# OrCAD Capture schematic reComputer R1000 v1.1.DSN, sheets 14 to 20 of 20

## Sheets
14 16 RS485_1& Isolated Power: size A3; rev: v1.0
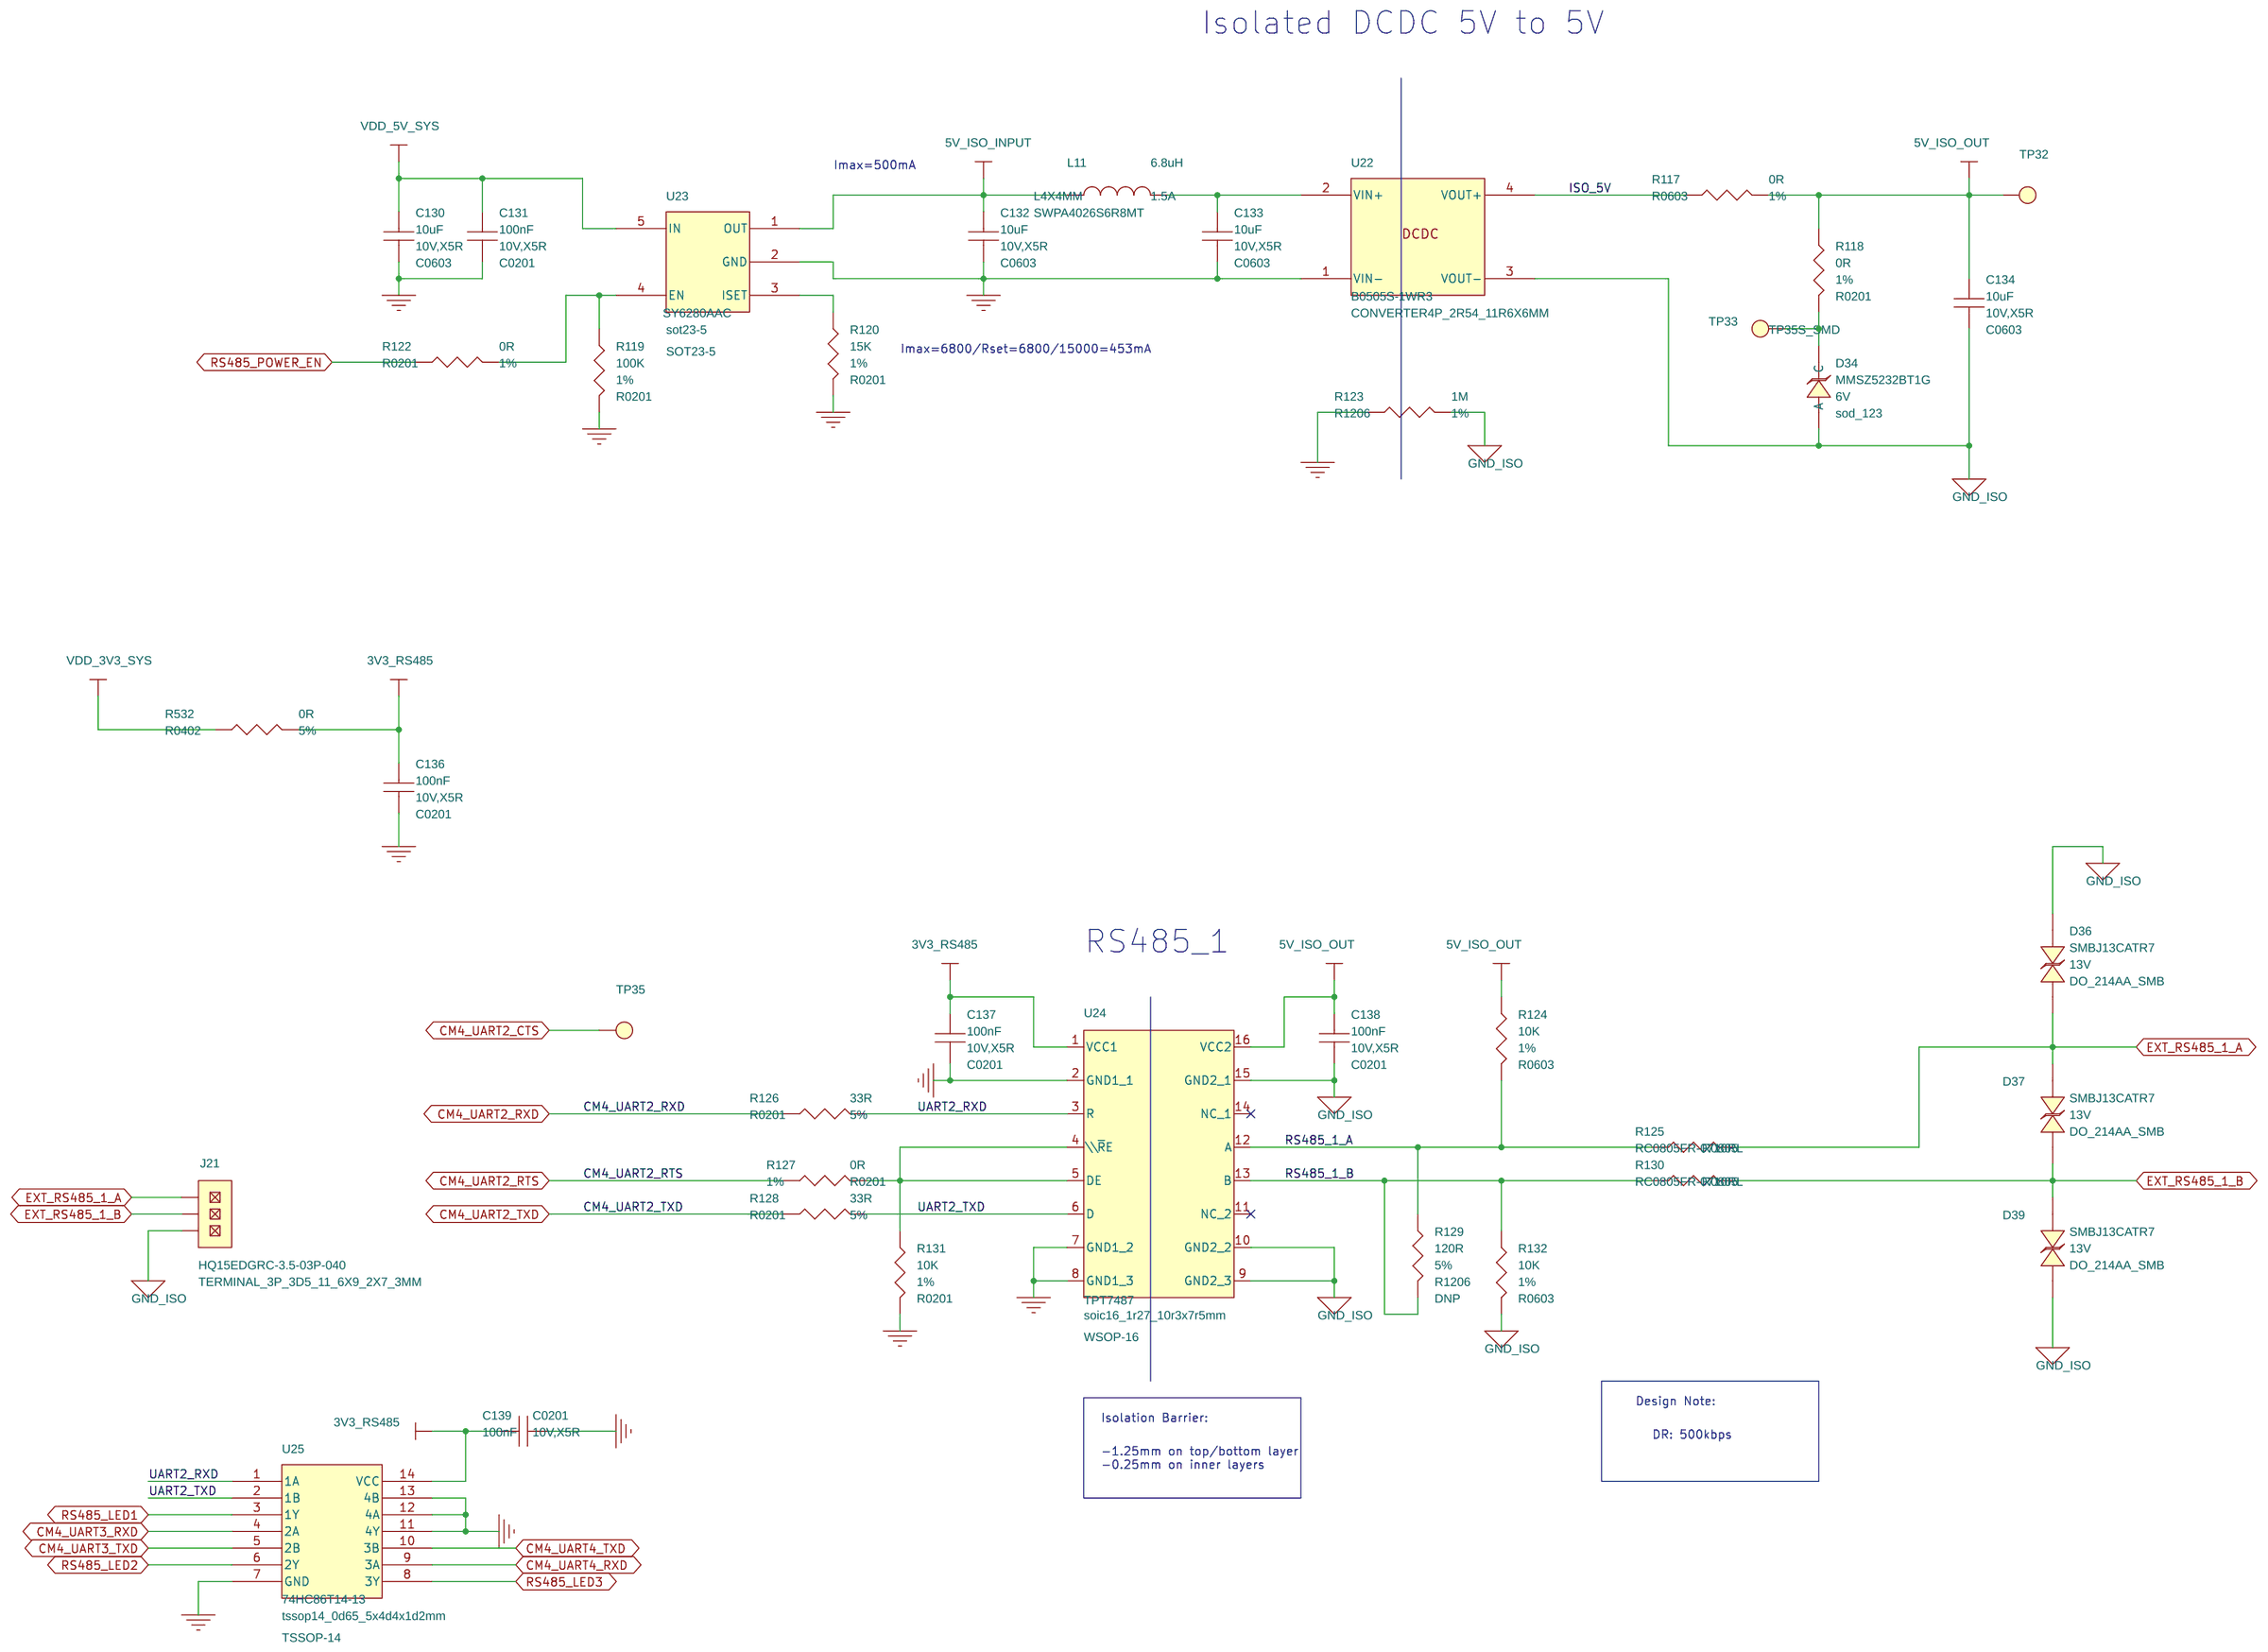
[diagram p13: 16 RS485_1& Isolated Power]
15 17 RS485 2&3: size A3; rev: v1.0
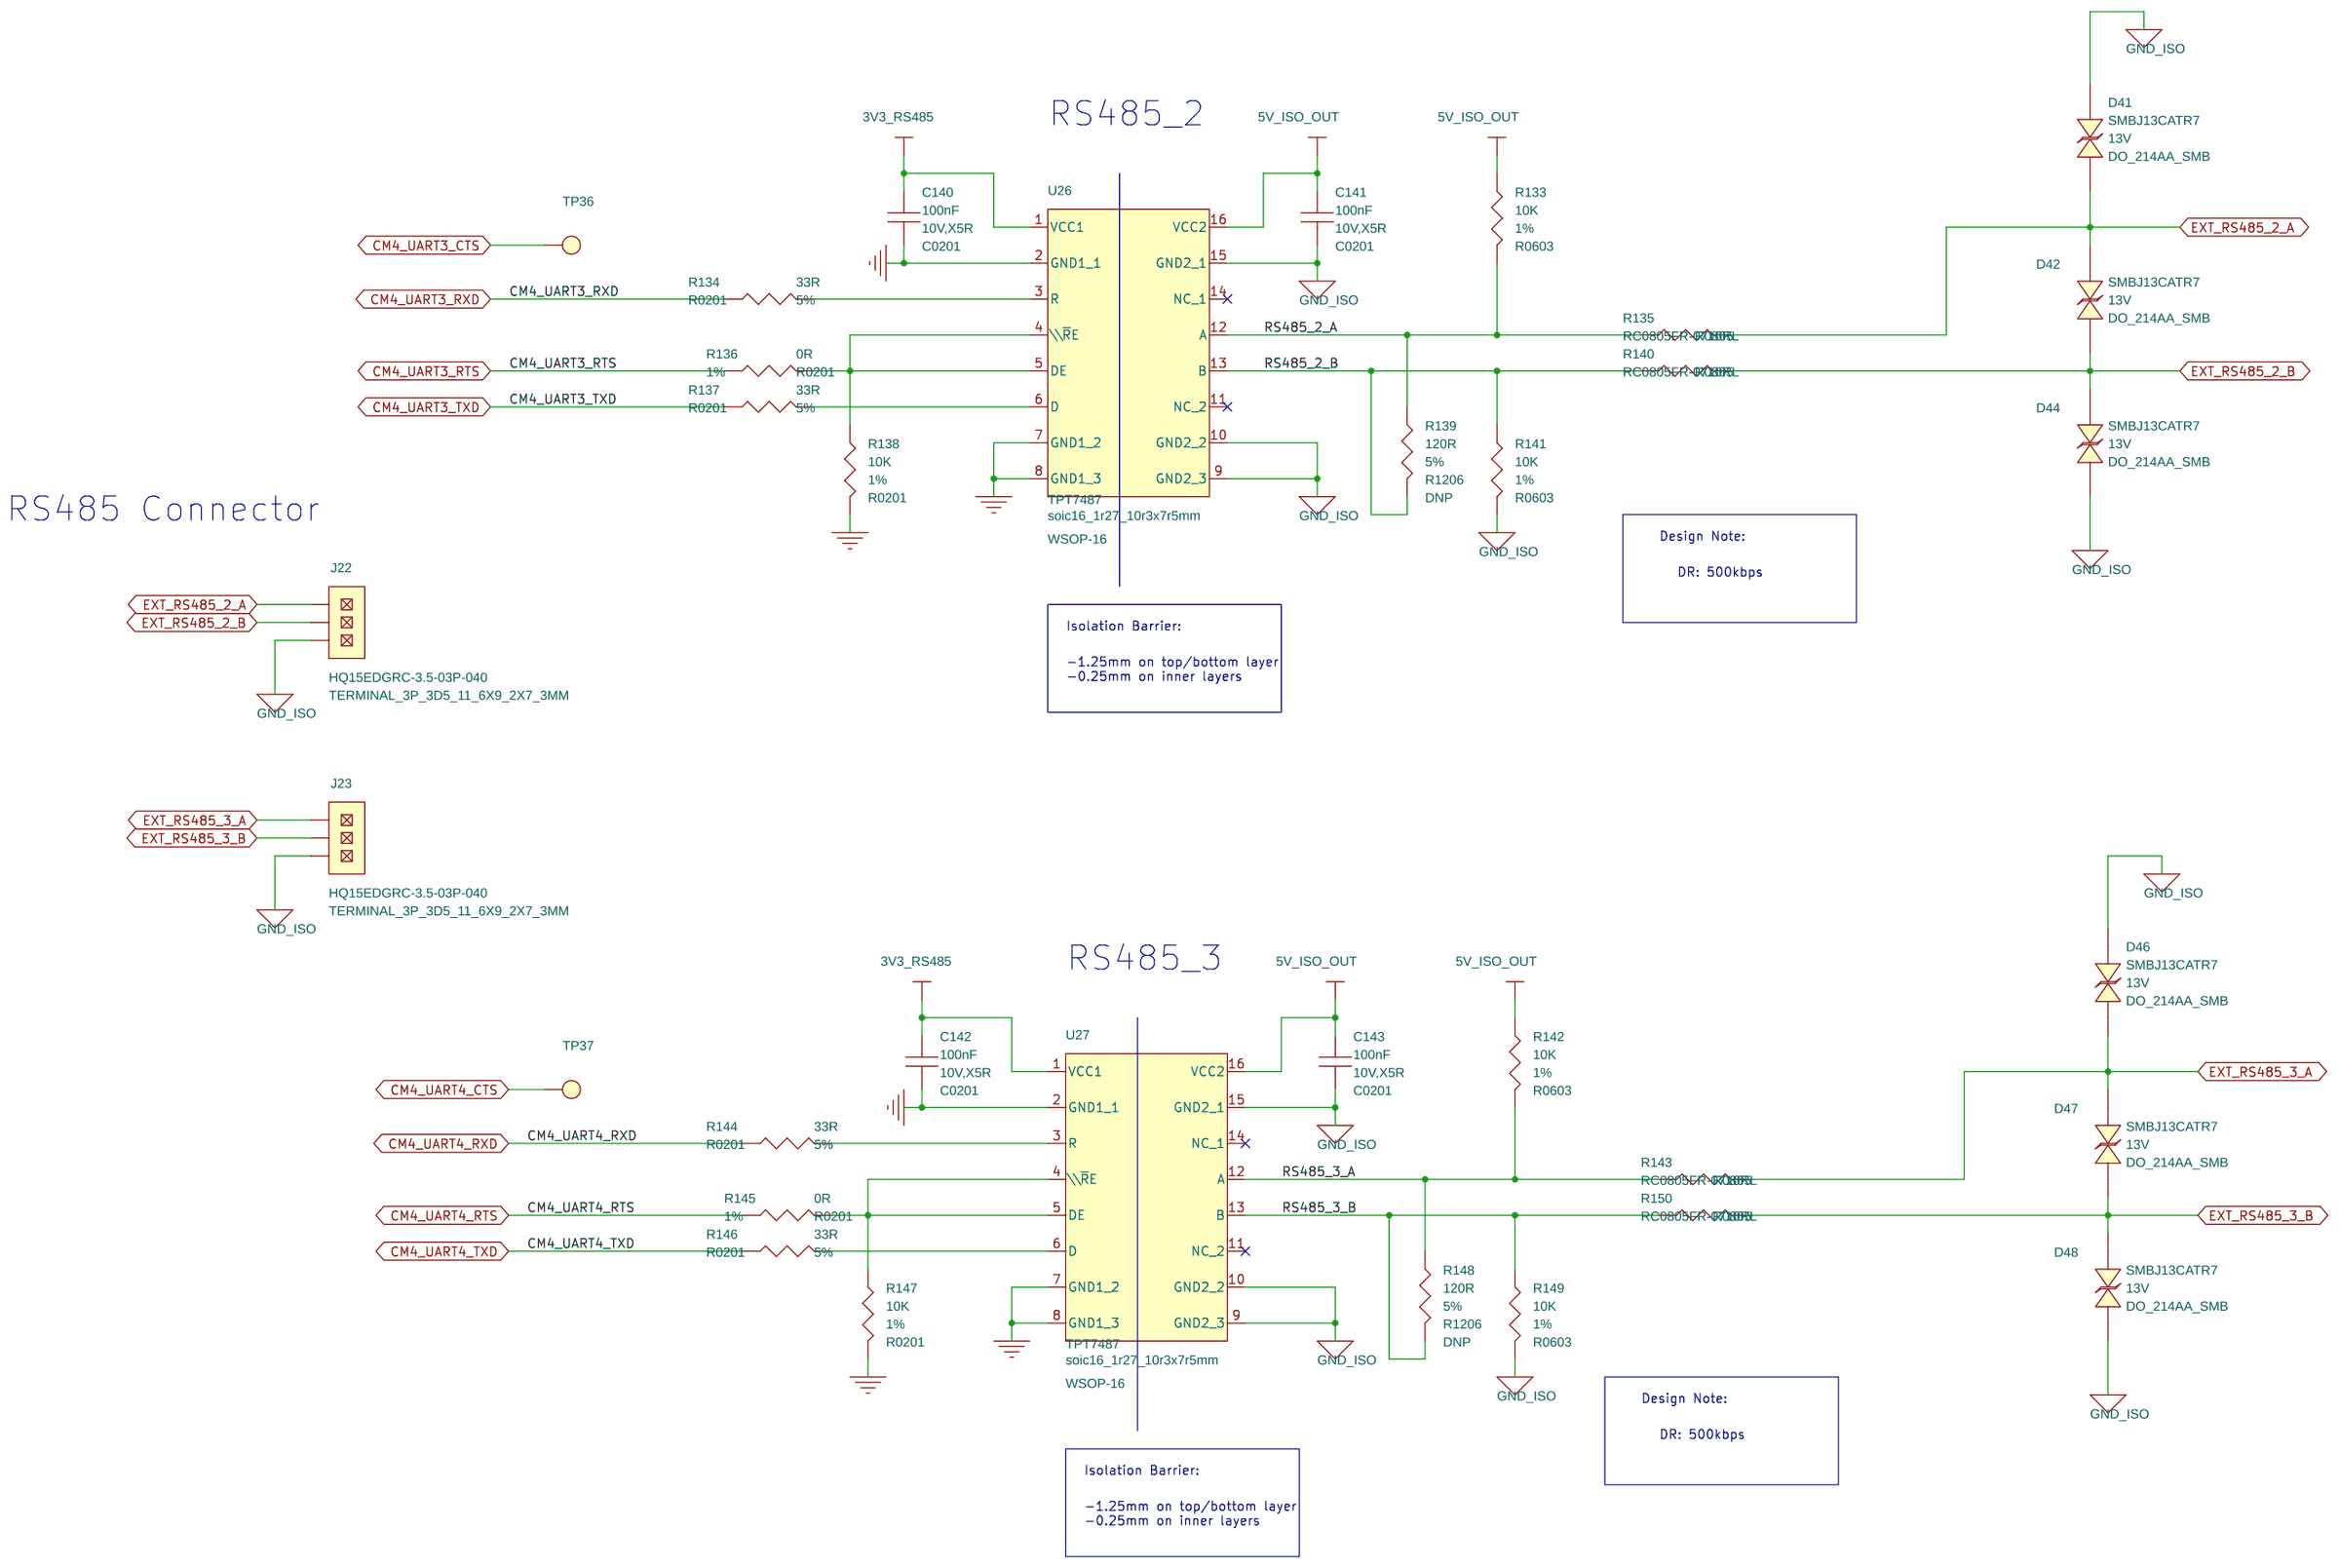
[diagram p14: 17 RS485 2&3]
16 18 Gigabit PoE: size A3; rev: v1.0
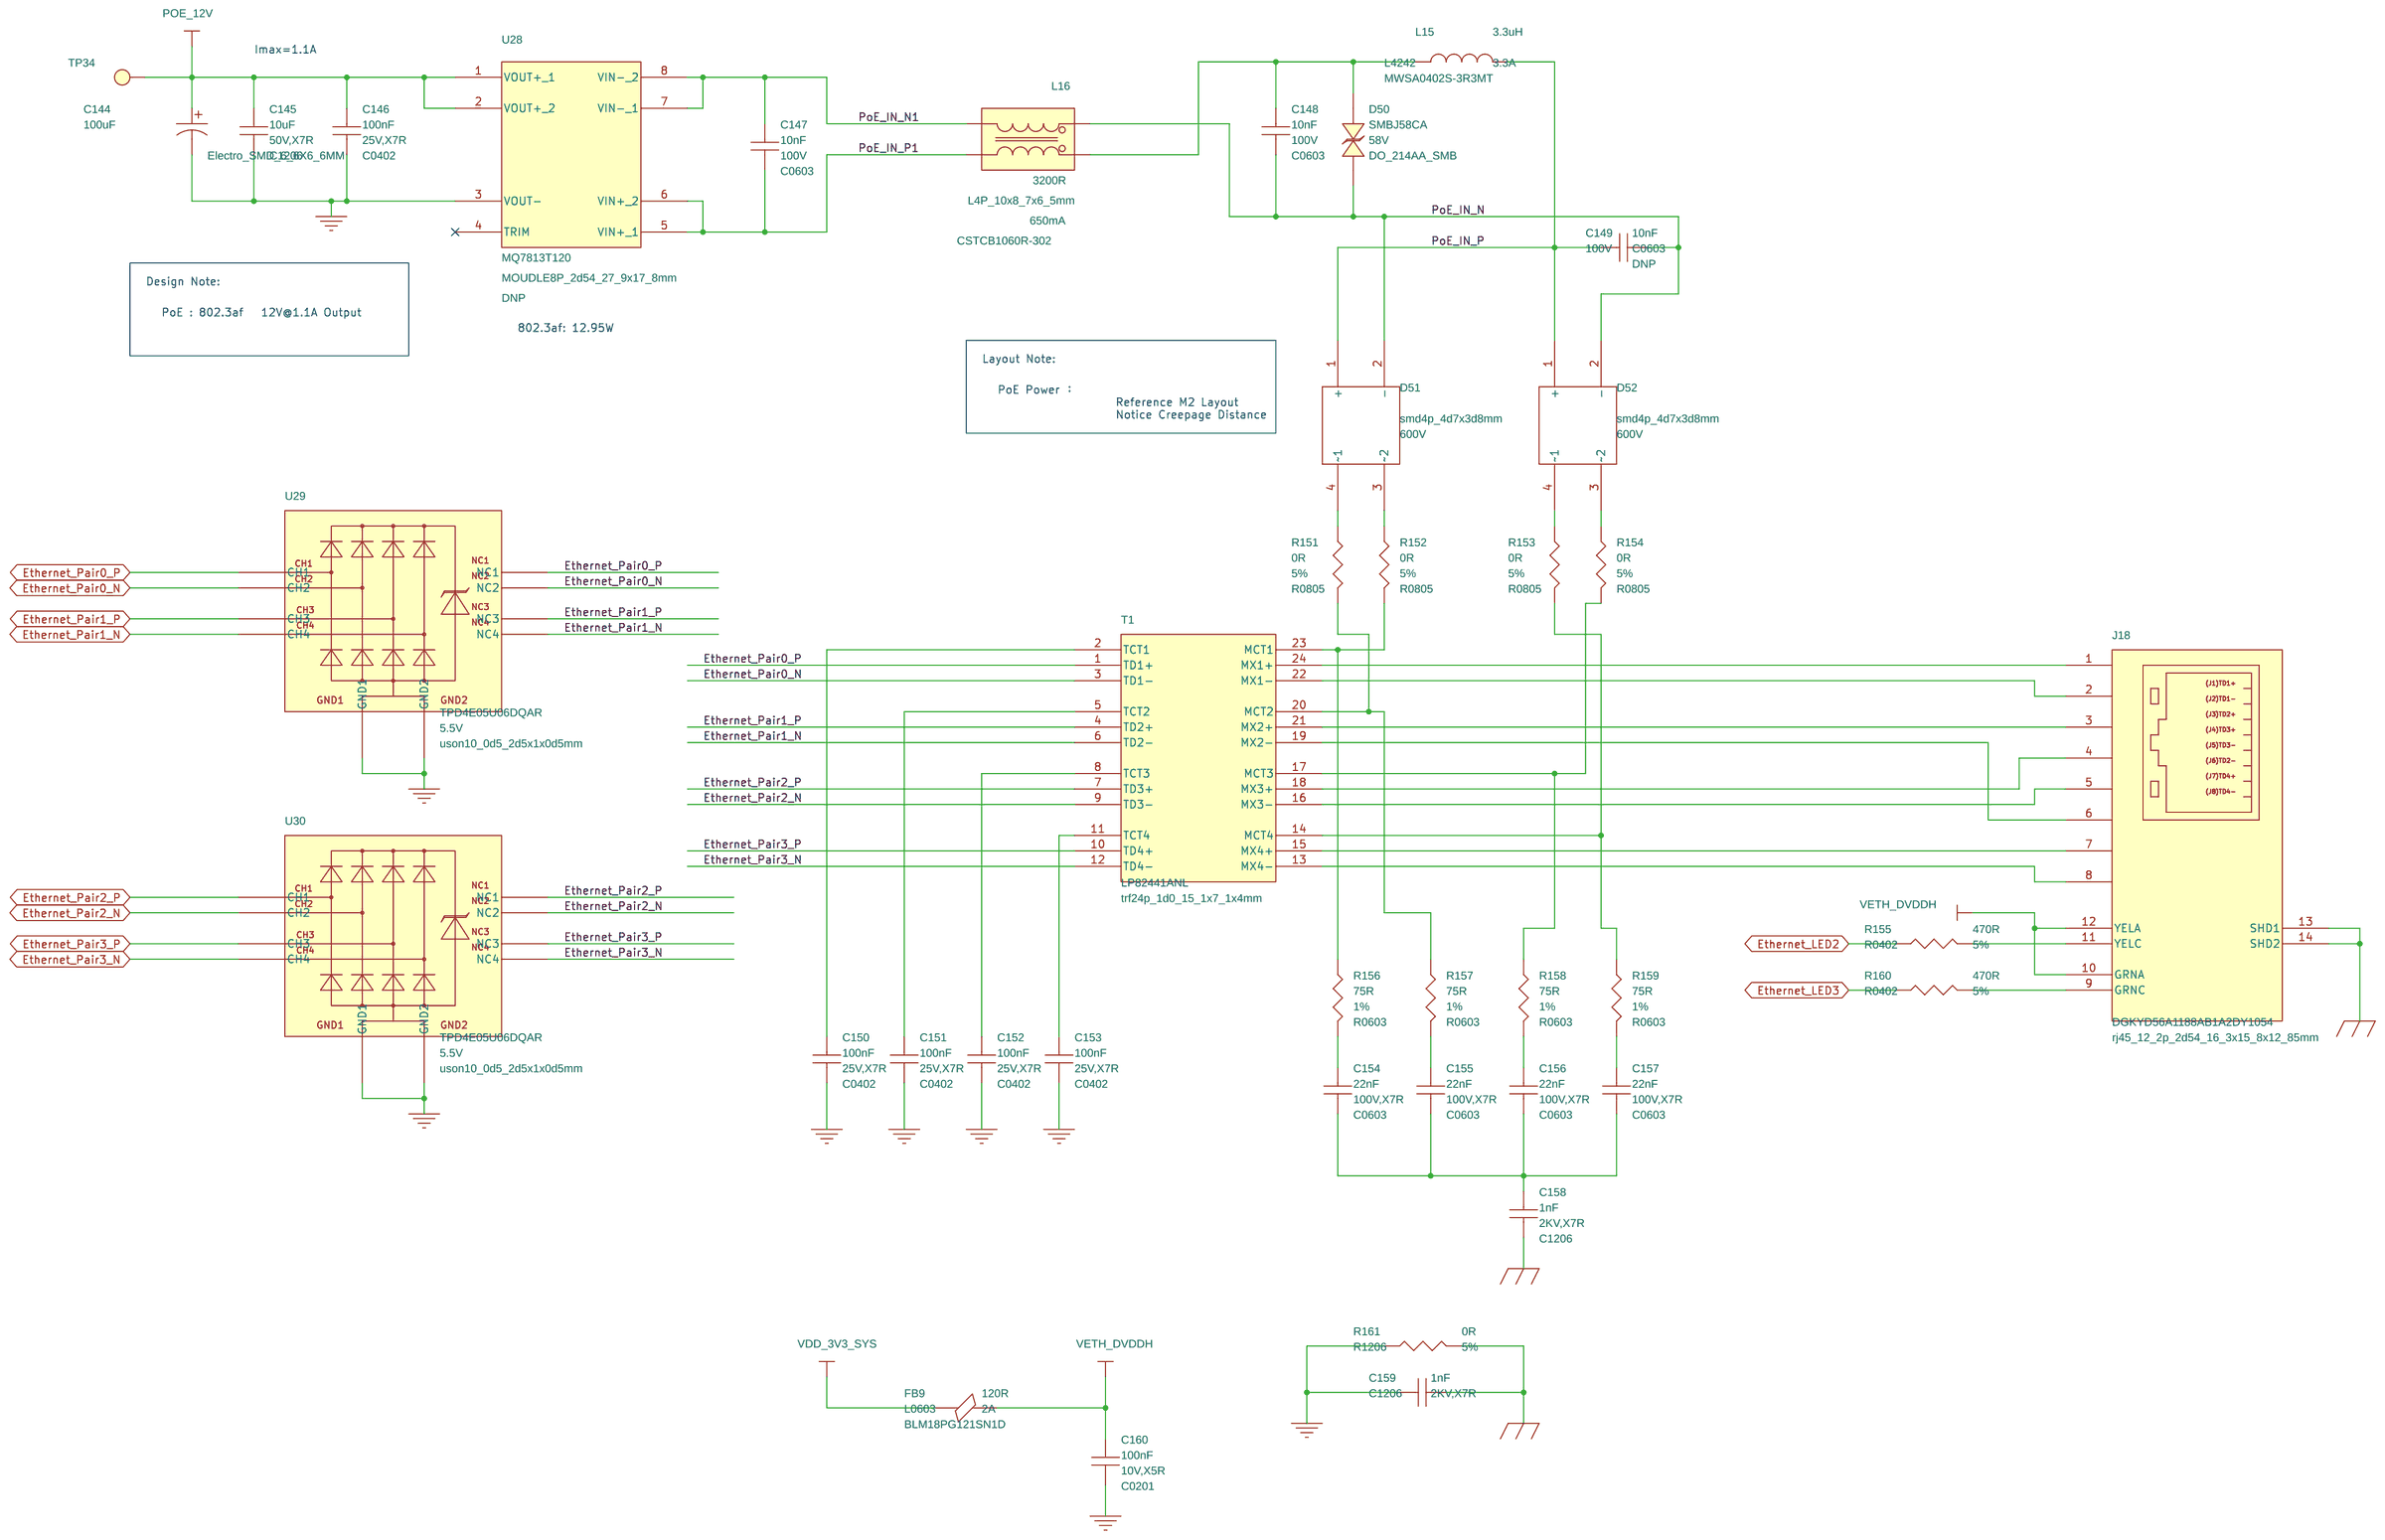
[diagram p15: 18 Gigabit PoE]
17 19 Expander Interface & LED: size A3; rev: v1.0
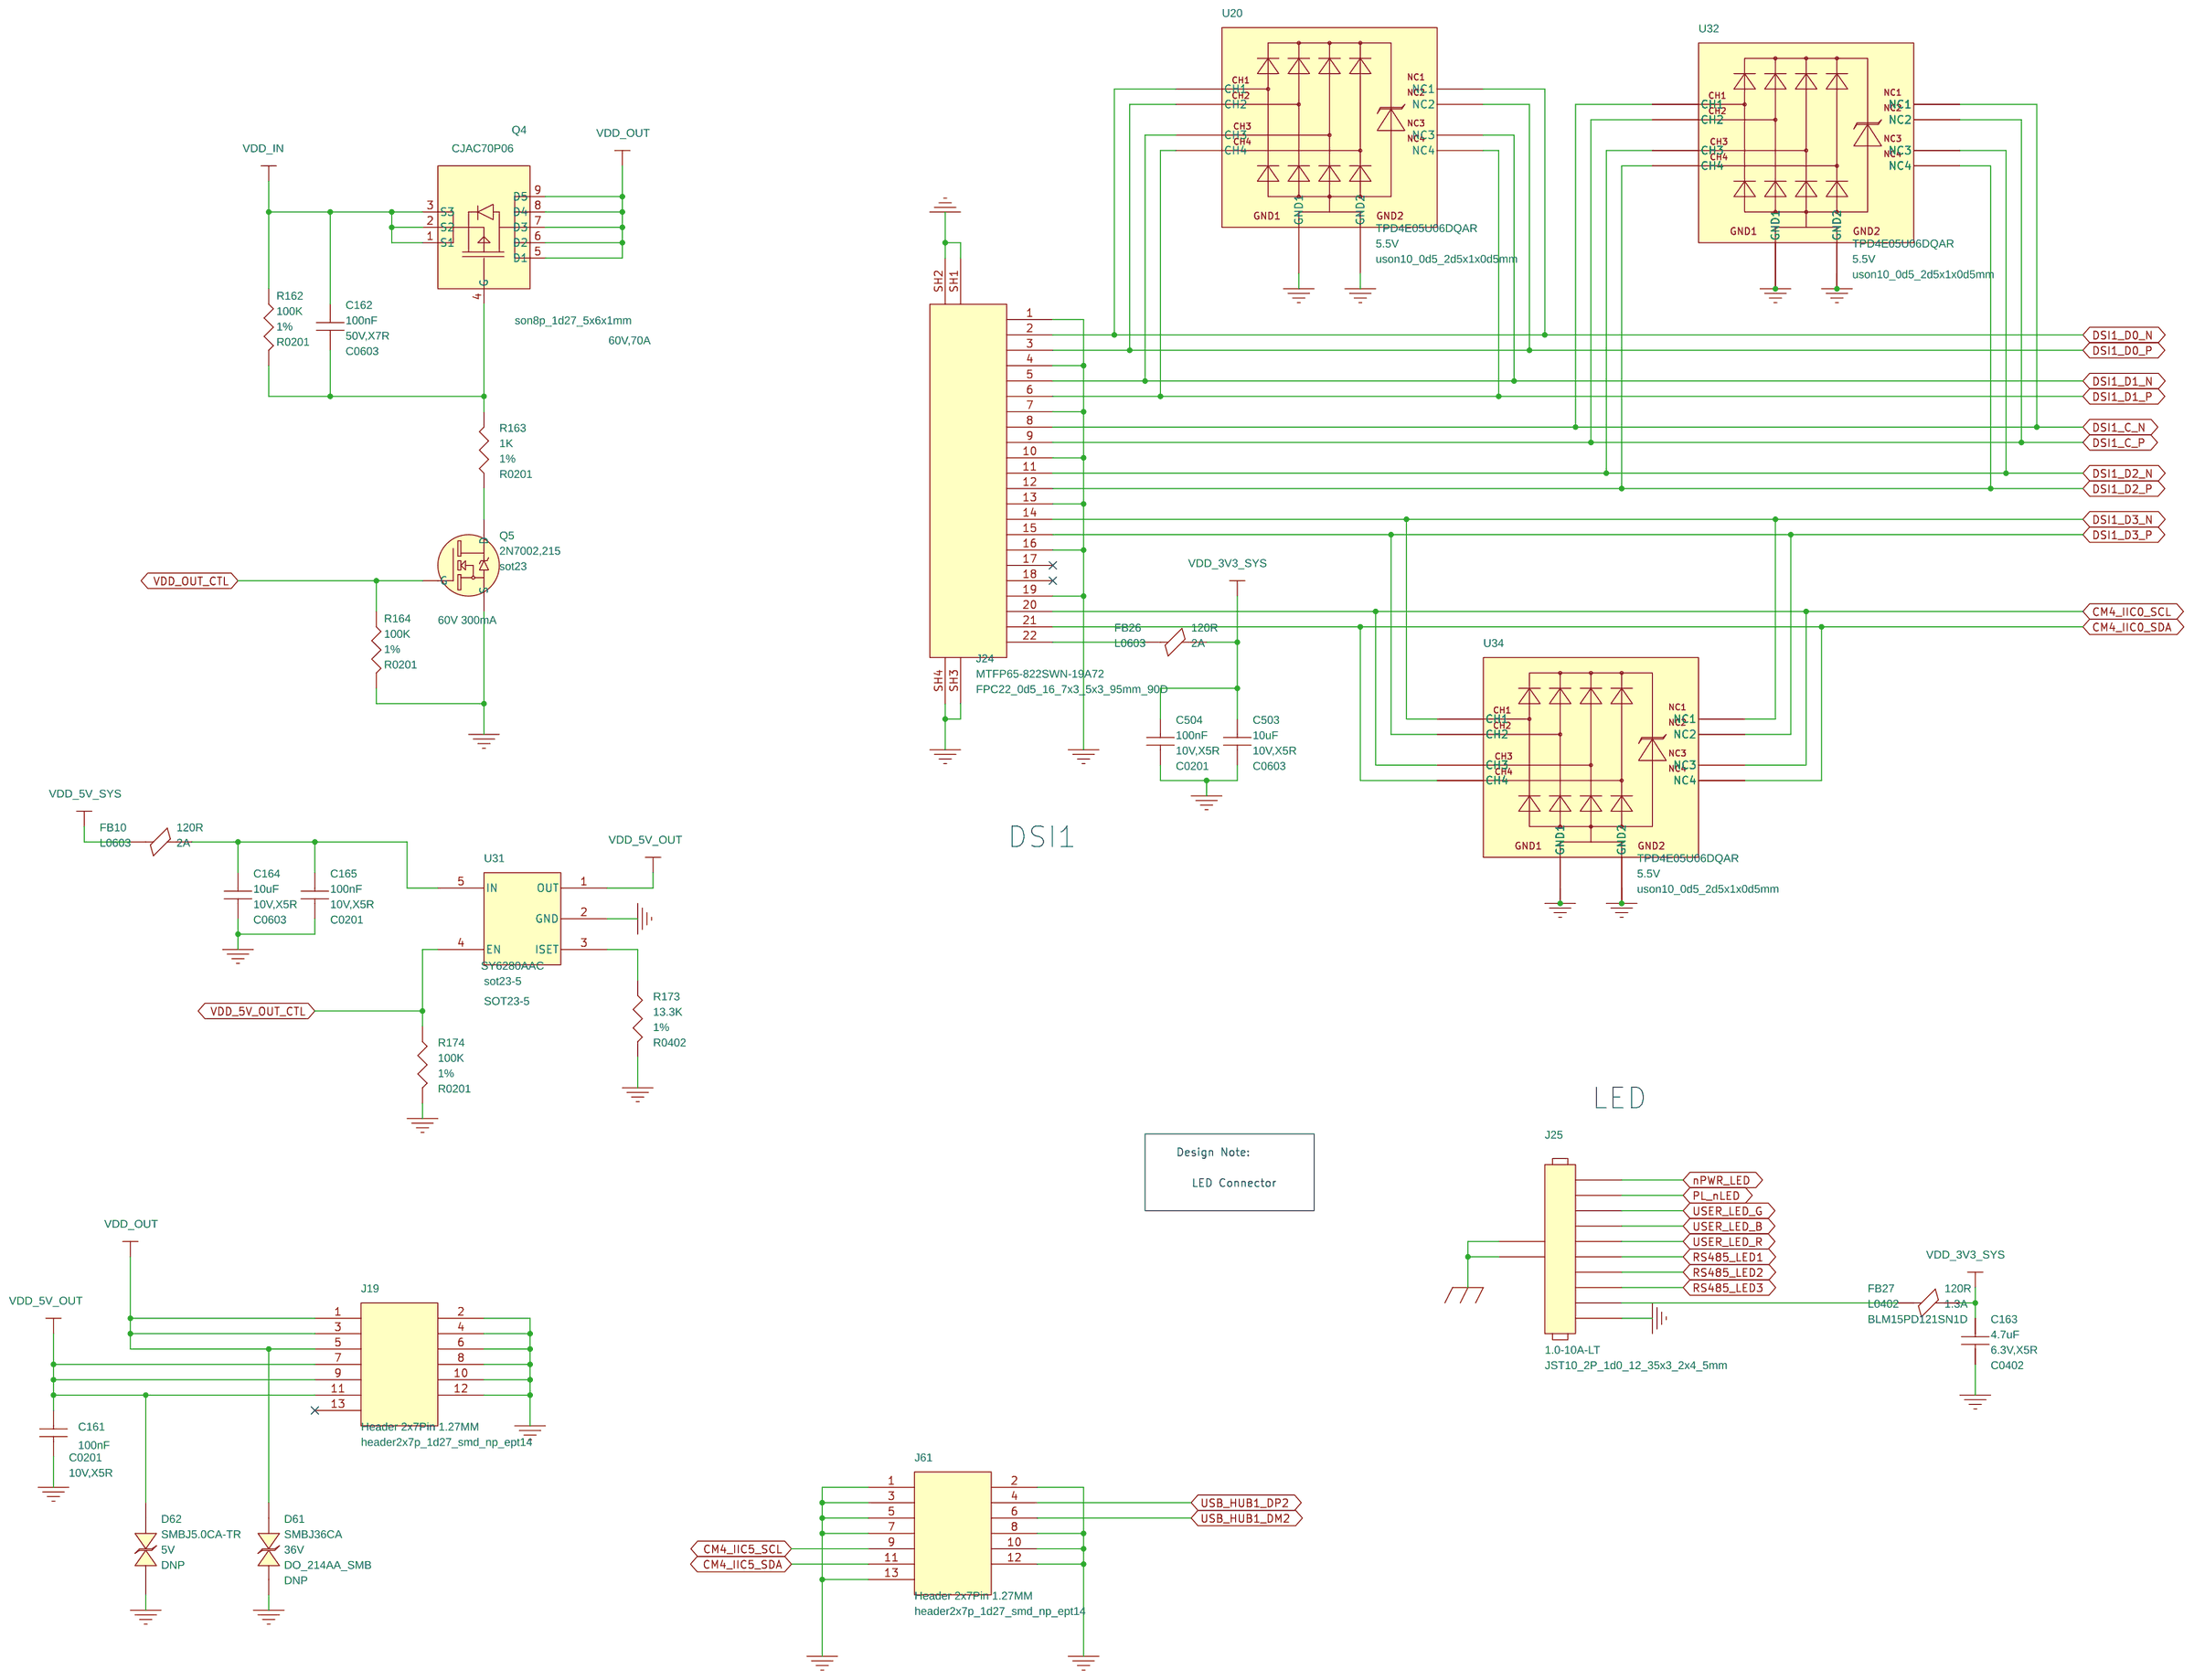
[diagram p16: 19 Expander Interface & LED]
18 20 M.2 SSD: size A3; rev: v1.0
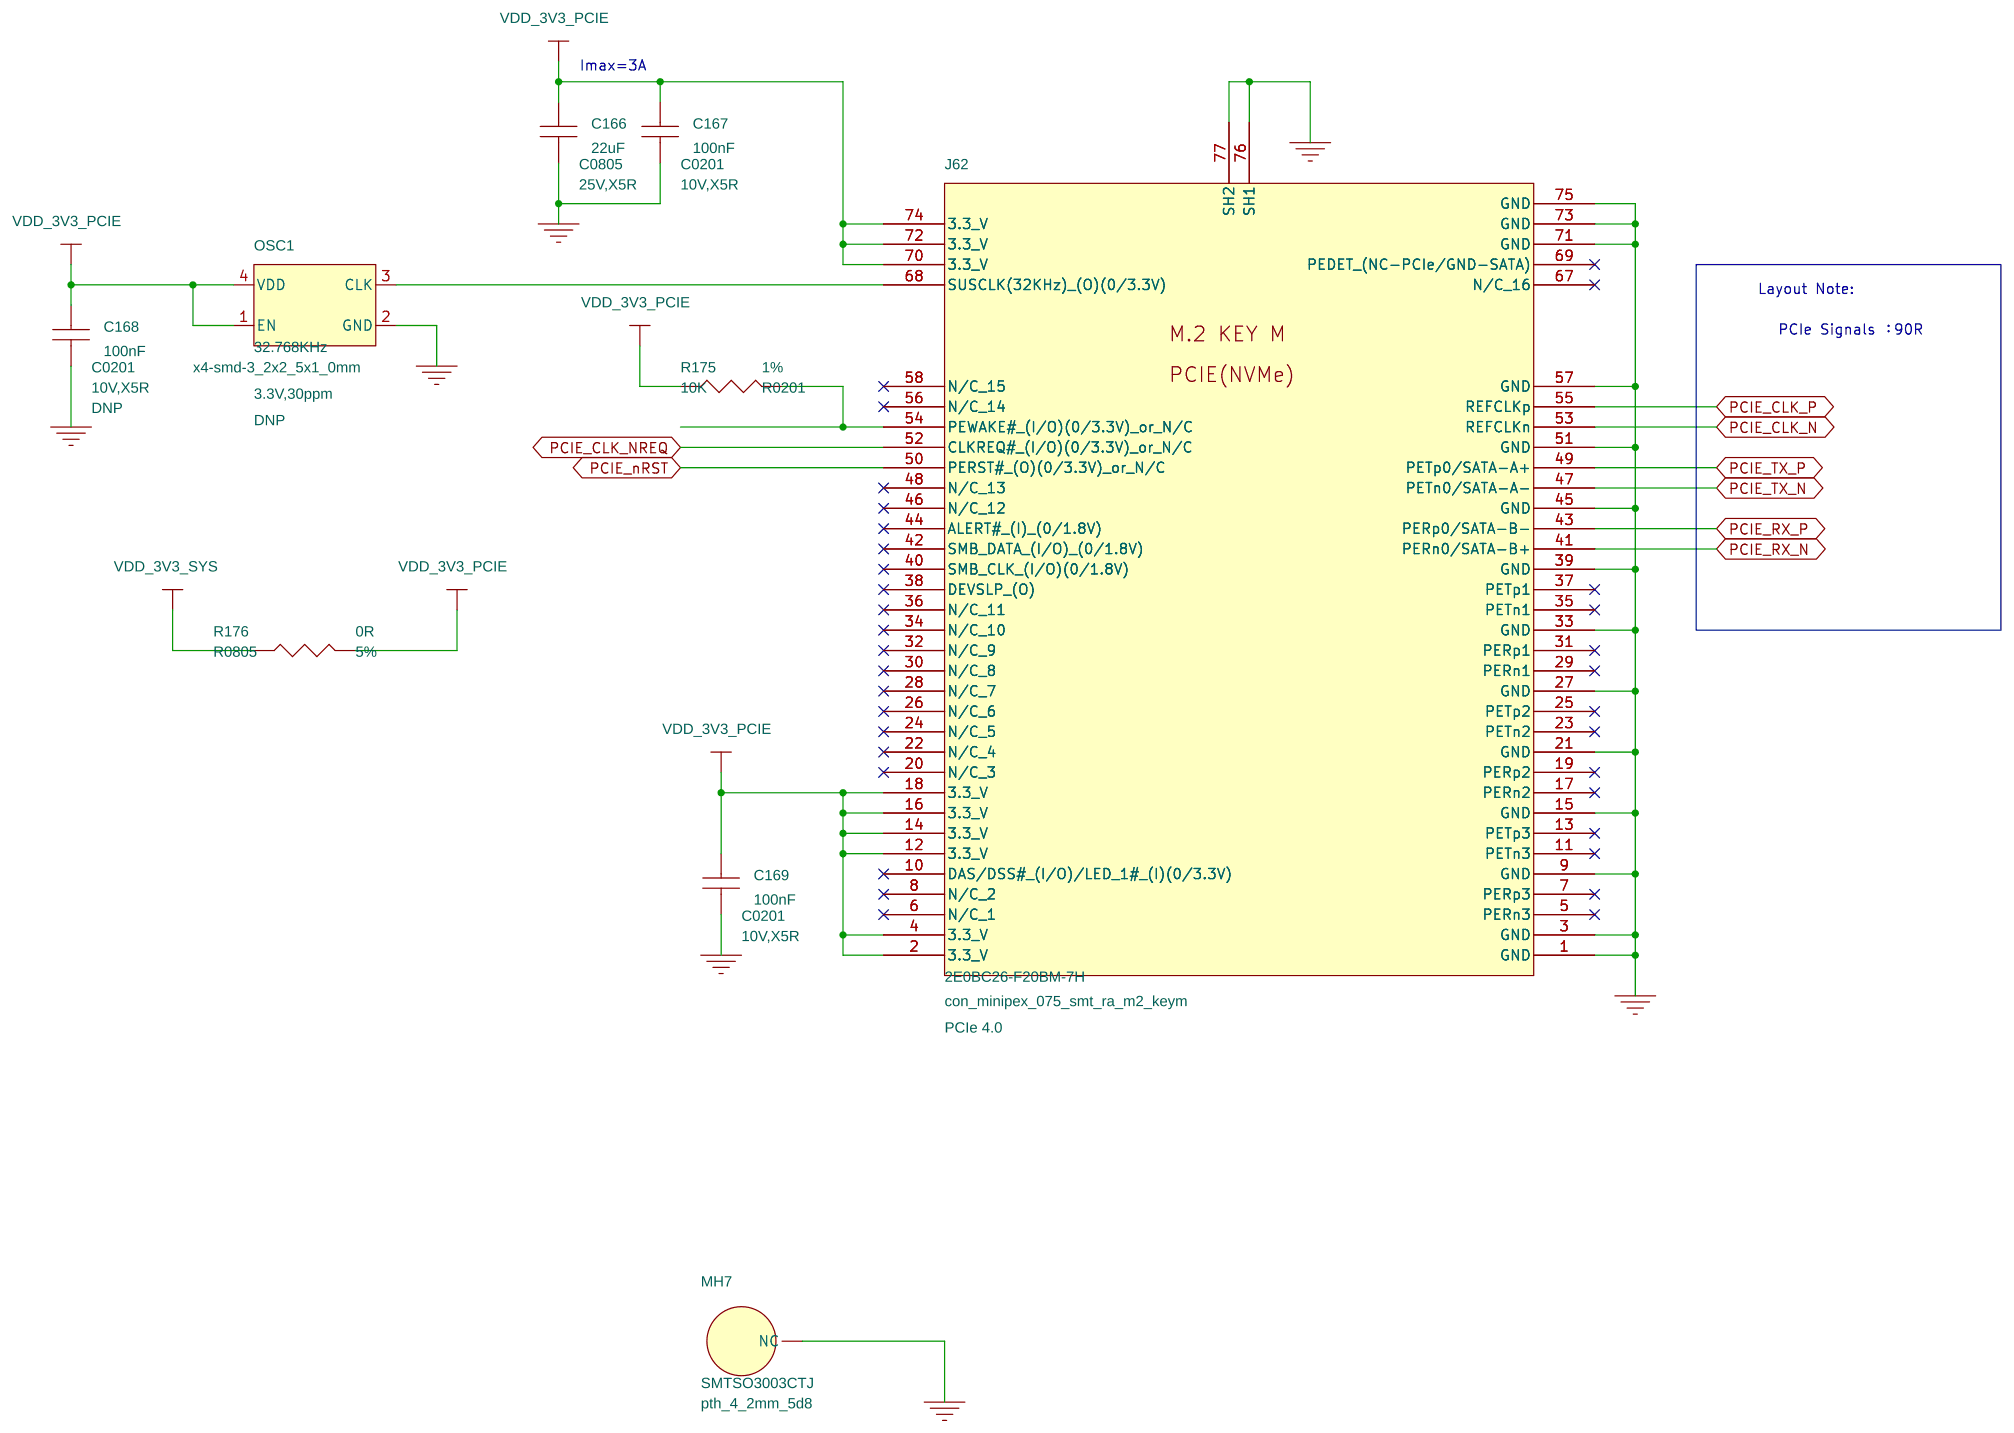
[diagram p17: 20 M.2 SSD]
19 01 Title / Revision History
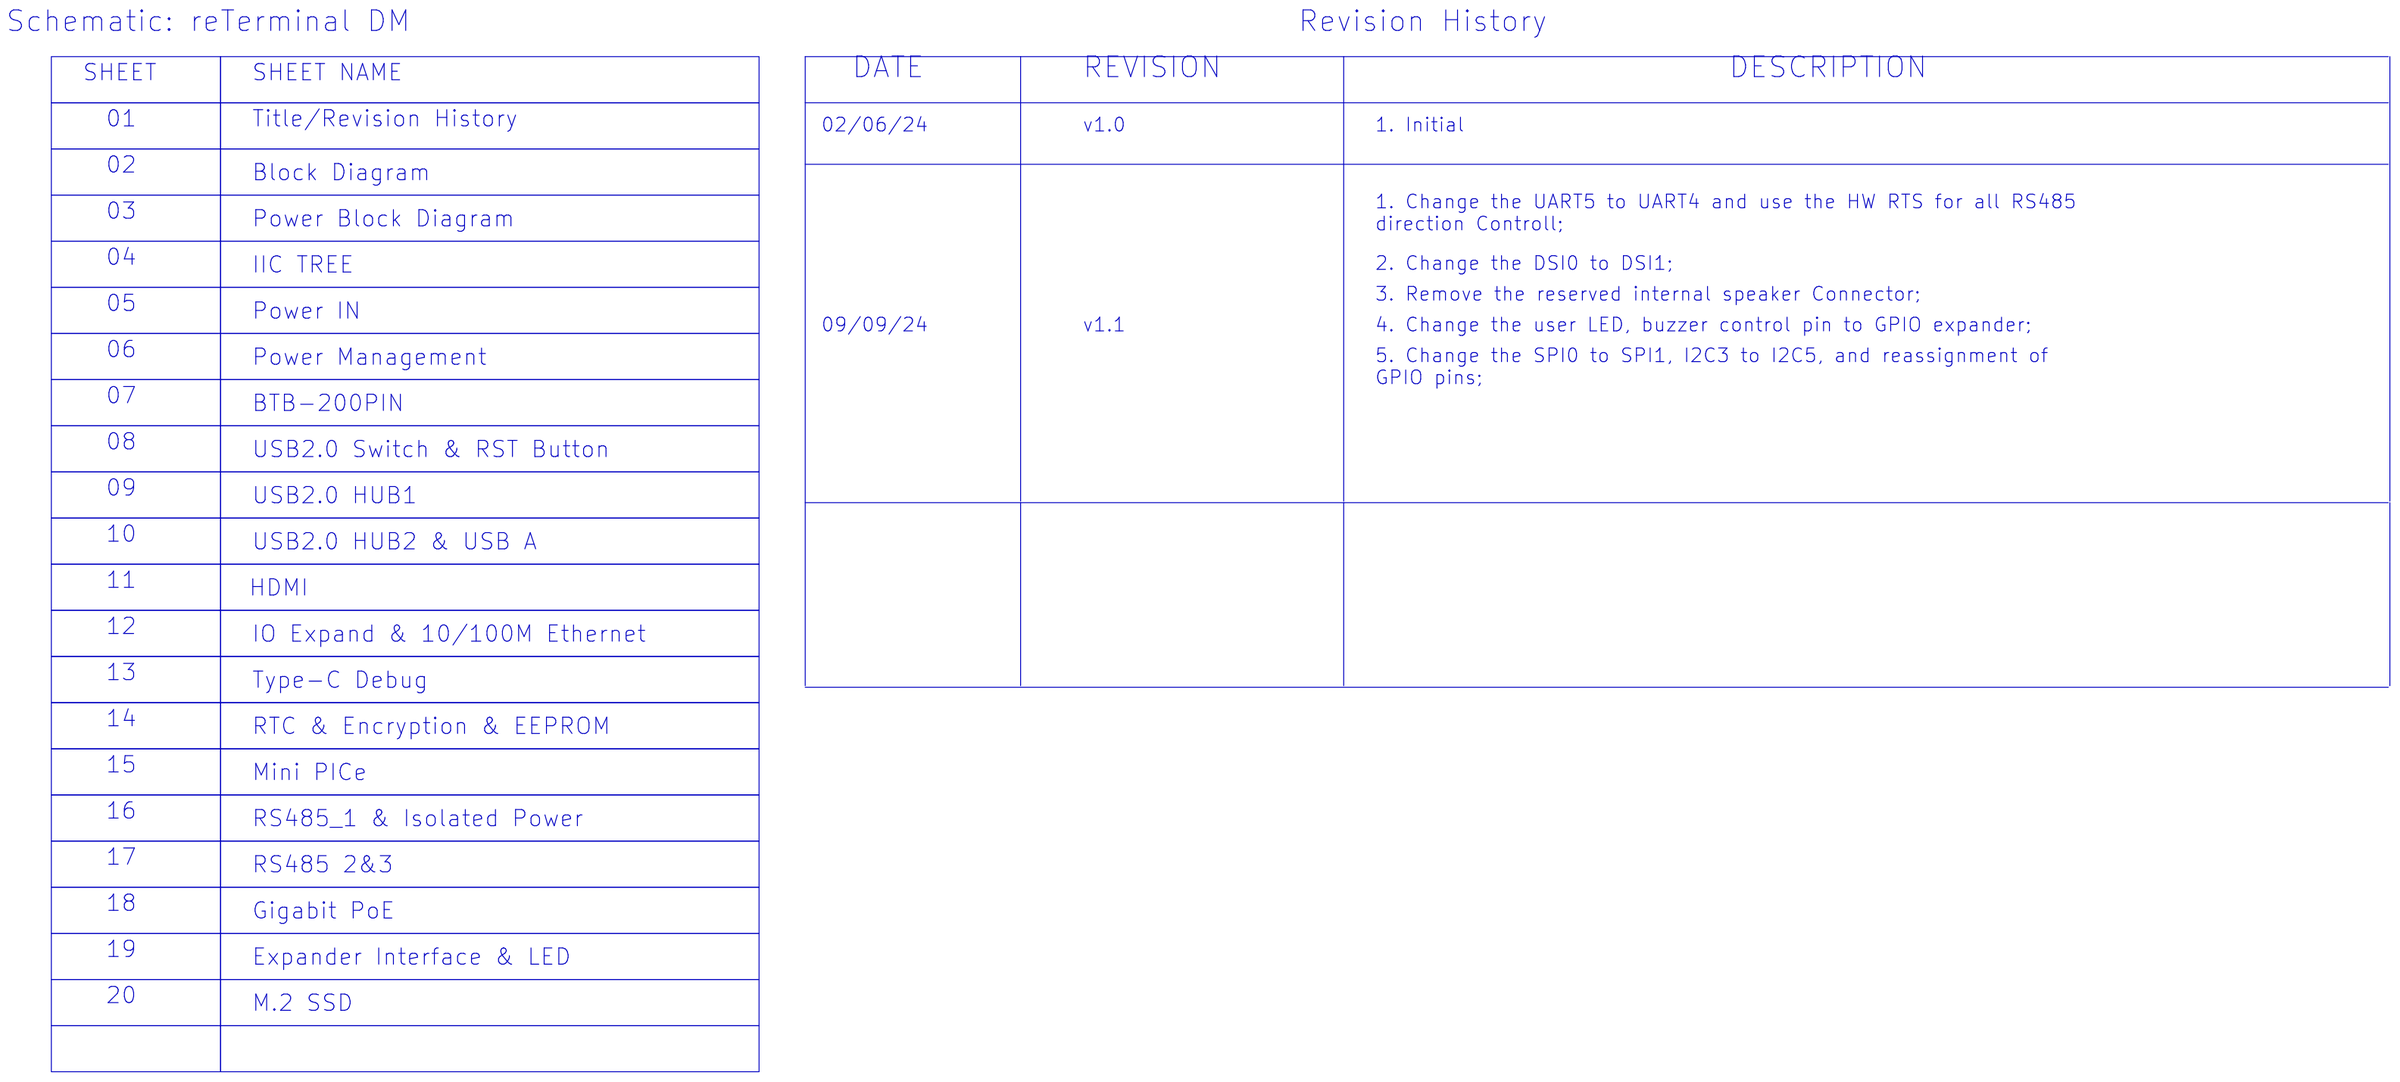
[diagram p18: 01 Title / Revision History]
20 12 IO Expan & 10/100M Ethernet: size A3; rev: v1.0

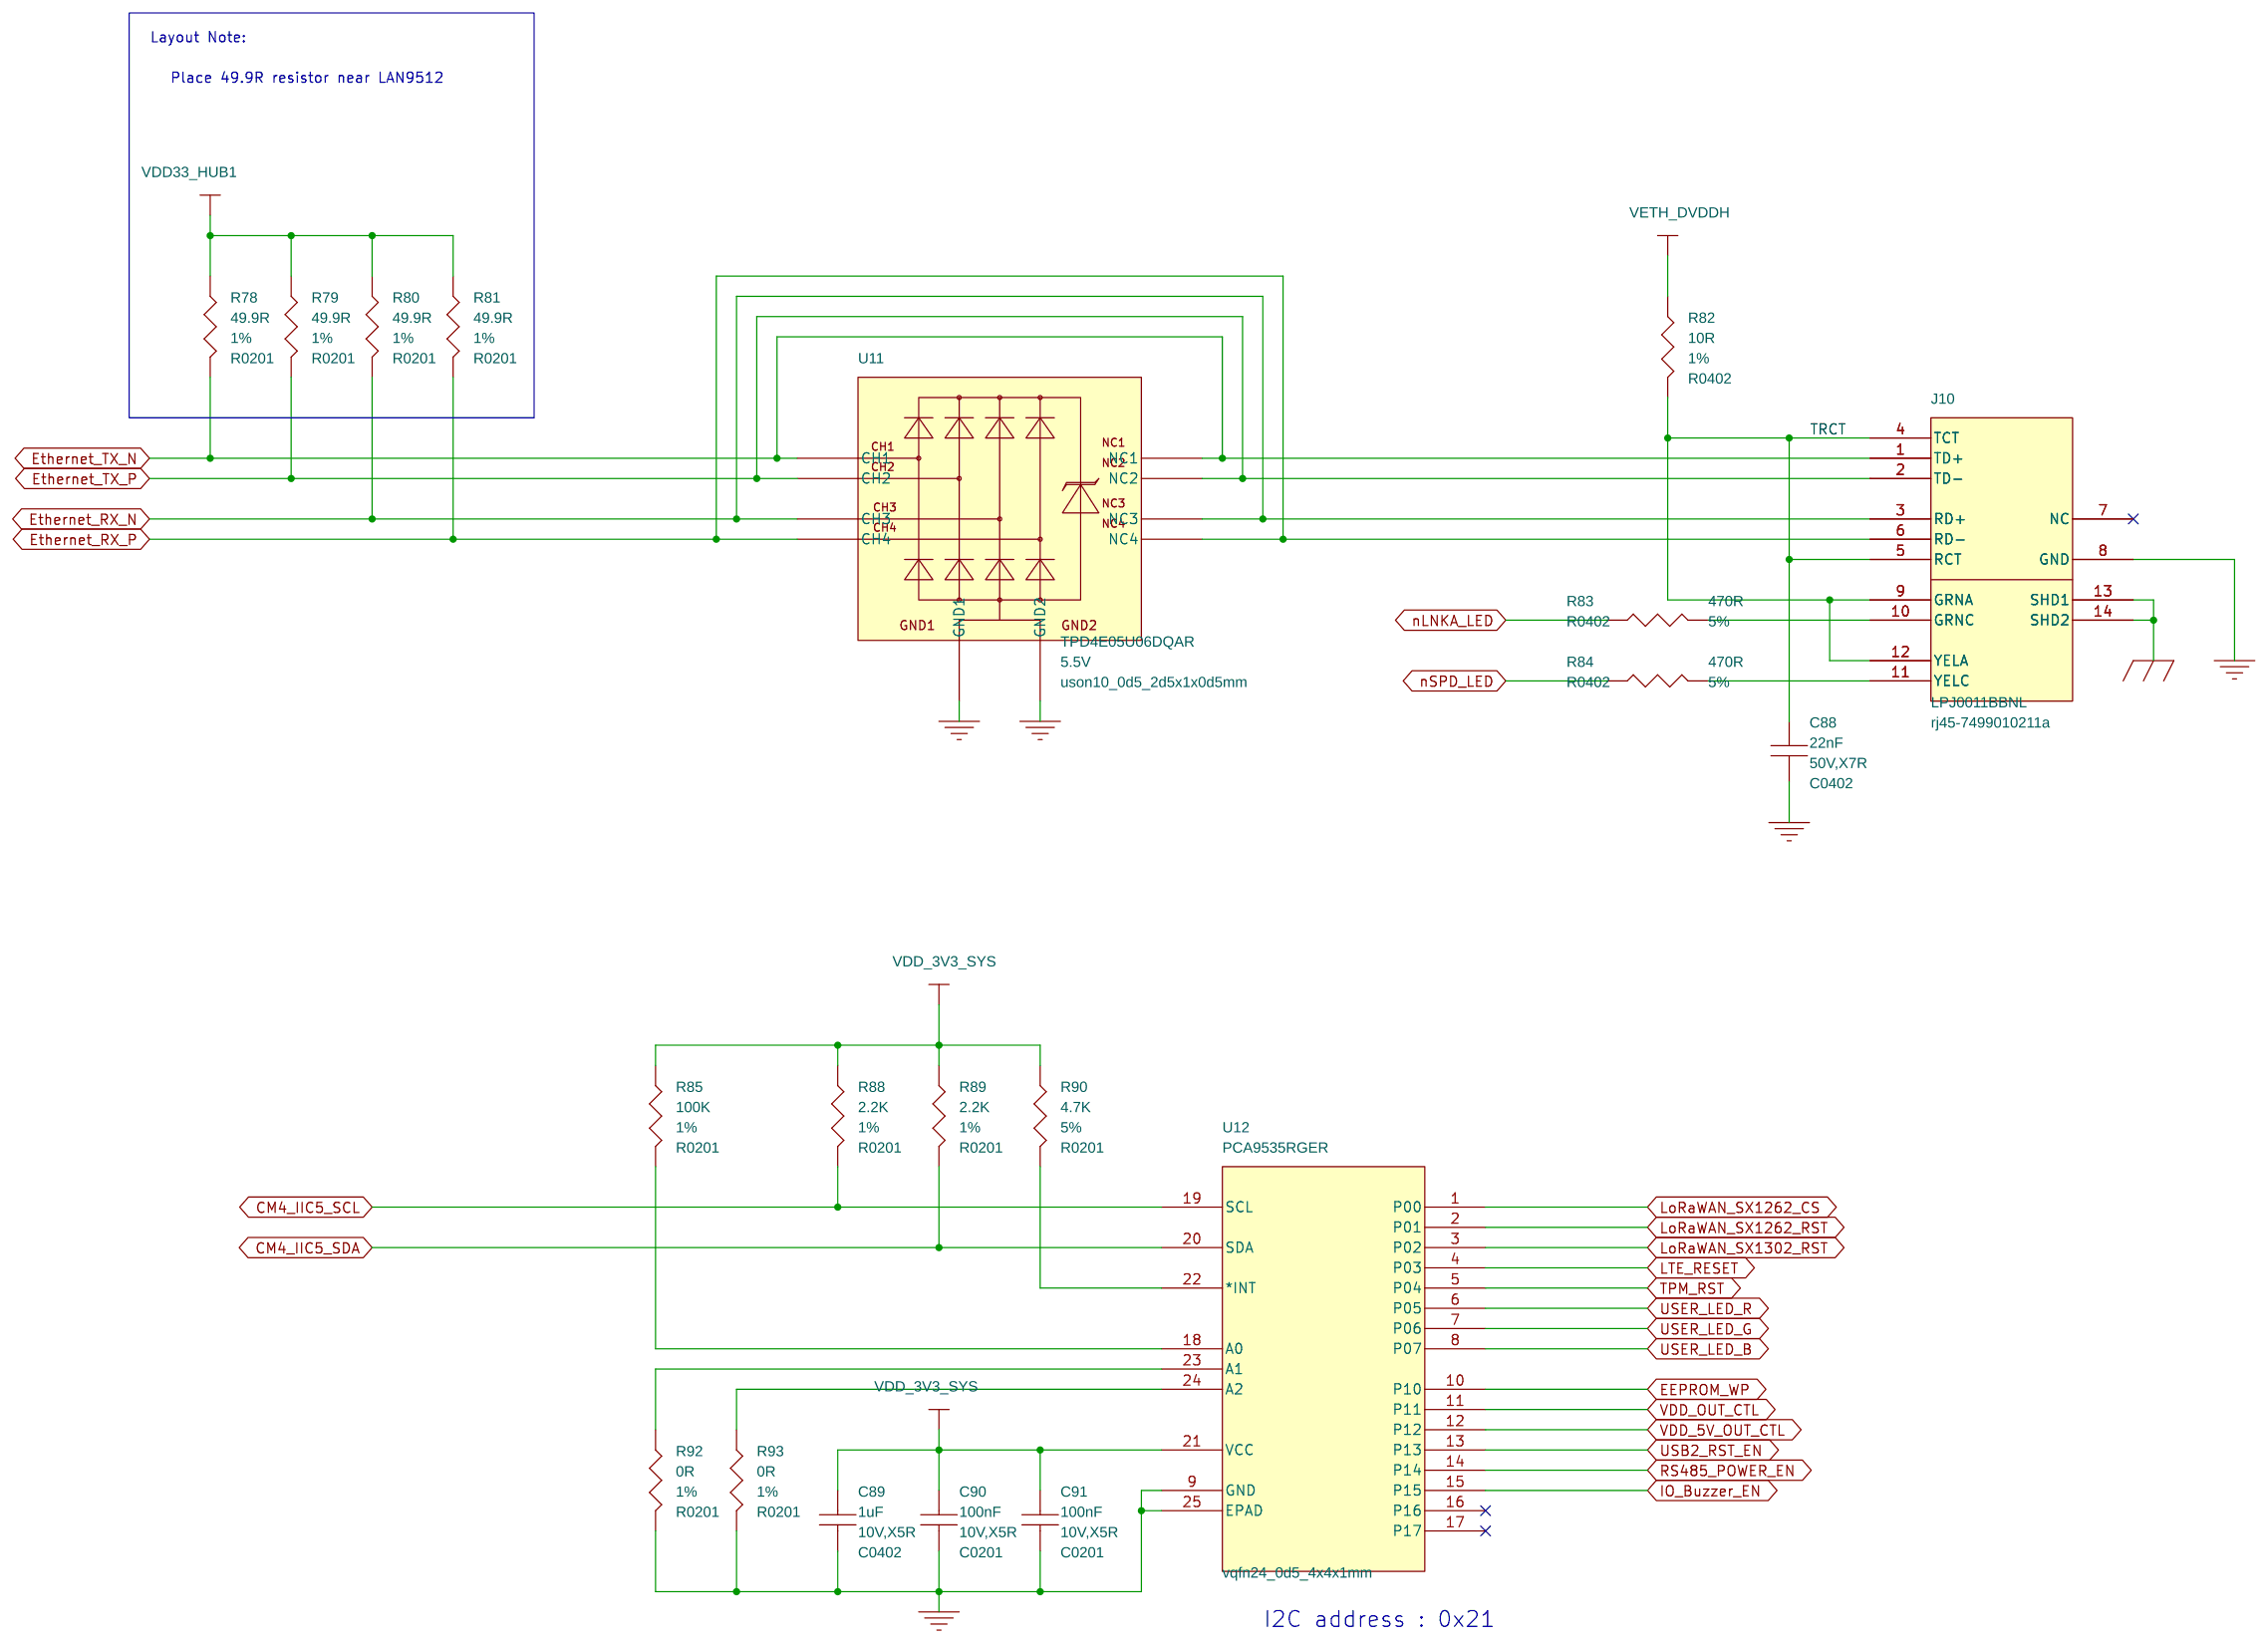
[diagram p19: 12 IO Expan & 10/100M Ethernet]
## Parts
sheet 12 IO Expan & 10/100M Ethernet
C88  22nF  [C0402]
C89  1uF  [C0402]
C90  100nF  [C0201]
C91  100nF  [C0201]
J10  LPJ0011BBNL  [rj45-7499010211a]
R78  49.9R  [R0201]
R79  49.9R  [R0201]
R80  49.9R  [R0201]
R81  49.9R  [R0201]
R82  10R  [R0402]
R83  470R  [R0402]
R84  470R  [R0402]
R85  100K  [R0201]
R88  2.2K  [R0201]
R89  2.2K  [R0201]
R90  4.7K  [R0201]
R92  0R  [R0201]
R93  0R  [R0201]
U11  TPD4E05U06DQAR  [uson10_0d5_2d5x1x0d5mm]
U12  PCA9535RGER  [vqfn24_0d5_4x4x1mm]
sheet 16 RS485_1& Isolated Power
C130  10uF  [C0603]
C131  100nF  [C0201]
C132  10uF  [C0603]
C133  10uF  [C0603]
C134  10uF  [C0603]
C136  100nF  [C0201]
C137  100nF  [C0201]
C138  100nF  [C0201]
C139  100nF  [C0201]
D34  MMSZ5232BT1G  [sod_123]
D36  SMBJ13CATR7  [DO_214AA_SMB]
D37  SMBJ13CATR7  [DO_214AA_SMB]
D39  SMBJ13CATR7  [DO_214AA_SMB]
J21  HQ15EDGRC-3.5-03P-040  [TERMINAL_3P_3D5_11_6X9_2X7_3MM]
L11  6.8uH  [L4X4MM]
R117  0R  [R0603]
R118  0R  [R0201]
R119  100K  [R0201]
R120  15K  [R0201]
R122  0R  [R0201]
R123  1M  [R1206]
R124  10K  [R0603]
R125  RC0805FR-0710RL  [R0805]
R126  33R  [R0201]
R127  0R  [R0201]
R128  33R  [R0201]
R129  120R  [R1206]
R130  RC0805FR-0710RL  [R0805]
R131  10K  [R0201]
R132  10K  [R0603]
R532  0R  [R0402]
TP32  Test Point  [TP35S_SMD]
TP33  Test Point  [TP35S_SMD]
TP35  Test Point  [TP35S_SMD]
U22  B0505S-1WR3  [CONVERTER4P_2R54_11R6X6MM]
U23  SY6280AAC  [sot23-5]
U24  TPT7487  [soic16_1r27_10r3x7r5mm]
U25  74HC86T14-13  [tssop14_0d65_5x4d4x1d2mm]
sheet 17 RS485 2&3
C140  100nF  [C0201]
C141  100nF  [C0201]
C142  100nF  [C0201]
C143  100nF  [C0201]
D41  SMBJ13CATR7  [DO_214AA_SMB]
D42  SMBJ13CATR7  [DO_214AA_SMB]
D44  SMBJ13CATR7  [DO_214AA_SMB]
D46  SMBJ13CATR7  [DO_214AA_SMB]
D47  SMBJ13CATR7  [DO_214AA_SMB]
D48  SMBJ13CATR7  [DO_214AA_SMB]
J22  HQ15EDGRC-3.5-03P-040  [TERMINAL_3P_3D5_11_6X9_2X7_3MM]
J23  HQ15EDGRC-3.5-03P-040  [TERMINAL_3P_3D5_11_6X9_2X7_3MM]
R133  10K  [R0603]
R134  33R  [R0201]
R135  RC0805FR-0710RL  [R0805]
R136  0R  [R0201]
R137  33R  [R0201]
R138  10K  [R0201]
R139  120R  [R1206]
R140  RC0805FR-0710RL  [R0805]
R141  10K  [R0603]
R142  10K  [R0603]
R143  RC0805FR-0710RL  [R0805]
R144  33R  [R0201]
R145  0R  [R0201]
R146  33R  [R0201]
R147  10K  [R0201]
R148  120R  [R1206]
R149  10K  [R0603]
R150  RC0805FR-0710RL  [R0805]
TP36  Test Point  [TP35S_SMD]
TP37  Test Point  [TP35S_SMD]
U26  TPT7487  [soic16_1r27_10r3x7r5mm]
U27  TPT7487  [soic16_1r27_10r3x7r5mm]
sheet 18 Gigabit PoE
C144  100uF  [Electro_SMD_6_6X6_6MM]
C145  10uF  [C1206]
C146  100nF  [C0402]
C147  10nF  [C0603]
C148  10nF  [C0603]
C149  10nF  [C0603]
C150  100nF  [C0402]
C151  100nF  [C0402]
C152  100nF  [C0402]
C153  100nF  [C0402]
C154  22nF  [C0603]
C155  22nF  [C0603]
C156  22nF  [C0603]
C157  22nF  [C0603]
C158  1nF  [C1206]
C159  1nF  [C1206]
C160  100nF  [C0201]
D50  SMBJ58CA  [DO_214AA_SMB]
D51  MB6S  [smd4p_4d7x3d8mm]
D52  MB6S  [smd4p_4d7x3d8mm]
FB9  120R  [L0603]
J18  DGKYD56A1188AB1A2DY1054  [rj45_12_2p_2d54_16_3x15_8x12_85mm]
L15  3.3uH  [L4242]
L16  3200R  [L4P_10x8_7x6_5mm]
R151  0R  [R0805]
R152  0R  [R0805]
R153  0R  [R0805]
R154  0R  [R0805]
R155  470R  [R0402]
R156  75R  [R0603]
R157  75R  [R0603]
R158  75R  [R0603]
R159  75R  [R0603]
R160  470R  [R0402]
R161  0R  [R1206]
T1  LP82441ANL  [trf24p_1d0_15_1x7_1x4mm]
TP34  Test Point  [TP35S_SMD]
U28  MQ7813T120  [MOUDLE8P_2d54_27_9x17_8mm]
U29  TPD4E05U06DQAR  [uson10_0d5_2d5x1x0d5mm]
U30  TPD4E05U06DQAR  [uson10_0d5_2d5x1x0d5mm]
sheet 19 Expander Interface & LED
C161  100nF  [C0201]
C162  100nF  [C0603]
C163  4.7uF  [C0402]
C164  10uF  [C0603]
C165  100nF  [C0201]
C503  10uF  [C0603]
C504  100nF  [C0201]
D61  SMBJ36CA  [DO_214AA_SMB]
D62  SMBJ5.0CA-TR  [DO_214AA_SMB]
FB10  120R  [L0603]
FB26  120R  [L0603]
FB27  120R  [L0402]
J19  Header 2x7Pin 1.27MM  [header2x7p_1d27_smd_np_ept14]
J24  MTFP65-822SWN-19A72  [FPC22_0d5_16_7x3_5x3_95mm_90D]
J25  1.0-10A-LT  [JST10_2P_1d0_12_35x3_2x4_5mm]
J61  Header 2x7Pin 1.27MM  [header2x7p_1d27_smd_np_ept14]
Q4  CJAC70P06  [son8p_1d27_5x6x1mm]
Q5  2N7002,215  [sot23]
R162  100K  [R0201]
R163  1K  [R0201]
R164  100K  [R0201]
R173  13.3K  [R0402]
R174  100K  [R0201]
U20  TPD4E05U06DQAR  [uson10_0d5_2d5x1x0d5mm]
U31  SY6280AAC  [sot23-5]
U32  TPD4E05U06DQAR  [uson10_0d5_2d5x1x0d5mm]
U34  TPD4E05U06DQAR  [uson10_0d5_2d5x1x0d5mm]
sheet 20 M.2 SSD
C166  22uF  [C0805]
C167  100nF  [C0201]
C168  100nF  [C0201]
C169  100nF  [C0201]
J62  2E0BC26-F20BM-7H  [con_minipex_075_smt_ra_m2_keym]
MH7  SMTSO3003CTJ  [pth_4_2mm_5d8]
OSC1  32.768KHz  [x4-smd-3_2x2_5x1_0mm]
R175  10K  [R0201]
R176  0R  [R0805]

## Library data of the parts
C88 = CC: SMD CAP Ceramic 22nF-50V-10%-X7R;0402; Manufacturer: YAGEO; Manufacturer Part Number: CC0402KRX7R9BB223; PN: 302010242; Package Size: 0402; Rating: 50V,X7R; Status: ST; Temperature: -55°C to 125°C
C89 = CC: SMD CAP Ceramic 1uF-10V-10%-X5R;0402; Manufacturer: YAGEO; Manufacturer Part Number: CC0402KRX5R6BB105; PN: 302010040; Package Size: 0402; Part Type: Ceramic; Rating: 10V,X5R; Status: BeagleBone Carrier Board; Temperature: -55°C to 85°C
C90 C91 C131 C136 C139 C160 C165 C504 = CC: SMD CAP Ceramic 100nF-10V-10%-X5R;0201; CLASS: DISCRETE; Company Part Status: BeagleBone Carrier Board; Dielectric Type: Ceramic; Manufacturer: YAGEO; Manufacturer PN: CC0402KRX7R8BB104; Manufacturer Part Number: CC0201KRX5R6BB104; PN: 302010271; Package Size: 0201; Part Type: Ceramic; Rating: 10V,X5R; SIGNAL_MODEL: DEFAULT_CAPACITOR_100000pF_1_2; Status: ODYSSEY-i.MX8M; Temperature: -55°C to 85°C; Temperature Coefficient: X7R; Tolerance: 10%
J10 = RJ45_HanRun_HY911105T: DIP RJ45 W/P-10/100M;12P-21.25*15.93*13.3mm; Manufacturer: Link-PP; PN: 320140216; Status: Zola; Temperature: 0°C to 70°C
R78-R81 = R: SMD RES 49.9R-1%-1/20W;0201; Manufacturer: YAGEO; Manufacturer Part Number: RC0201FR-0749R9L; PN: 301012326; Package Size: 0201; Rating: 1%; Status: BeagleBone AI TDA4VM; Temperature: -55°C to 125°C
R82 = R: SMD RES 10R-1%-1/16W;0402; Manufacturer: YAGEO; Manufacturer Part Number: RC0402FR-0710RL; PN: 301010444; Package Size: 0402; Rating: 1%; Status: IOT Enabling Dongle Board; Temperature: -55°C to 155°C
R83 R84 R155 R160 = R: SMD RES 470R-5%-1/16W;0402; Manufacturer: YAGEO; Manufacturer Part Number: RC0402JR-07470RL; PN: 301010013; Package Size: 0402; Part Type: RES; Priority: A; Rating: 5%; Status: BeagleBone AI TDA4VM; Temperature: -55°C to 155°C
R85 R119 R162 R164 R174 = R: SMD RES 100K-±1%-1/20W;0201; CLASS: DISCRETE; Company Part Status: BeagleBone Carrier Board; Manufacturer: YAGEO; Manufacturer PN: RC0402FR-07100KL; Manufacturer Part Number: RC0201FR-07100KL; PN: 301010765; Package Size: 0201; Part Type: RES; Rated Power: 1/16W; Rating: 1%; Status: LR1110; Temperature: -55°C to 125°C
R88 R89 = R: SMD RES 2.2K-1%-1/20W;0201; CLASS: DISCRETE; Company Part Status: BeagleBone Carrier Board; Manufacturer: YAGEO; Manufacturer PN: RC0402FR-074K7L; Manufacturer Part Number: RC0201FR-072K2L; PN: 301010753; Package Size: 0201; Part Type: RES; Rated Power: 1/16W; Rating: 1%; Status: BeagleBone AI TDA4VM; Temperature: -55°C to 125°C
R90 = R: SMD RES;4.7K-5%-1/20W;0201; CLASS: DISCRETE; Company Part Status: BeagleBone Carrier Board; Manufacturer: YAGEO; Manufacturer PN: RC0402FR-074K7L; Manufacturer Part Number: RC0201JR-074K7L; PN: 301010677; Package Size: 0201; Part Type: RES; Rated Power: 1/16W; Rating: 5%; Status: BeagleV-Ahead; Temperature: -55°C to 125°C
R92 R93 R127 R136 R145 = R: SMD RES 0R-±1%-1/20W;0201; CLASS: DISCRETE; Company Part Status: BeagleBone Carrier Board; Manufacturer: YAGEO; Manufacturer PN: RC0402JR-070RL; Manufacturer Part Number: RC0201FR-070RL; PN: 301010525; Package Size: 0201; Part Type: RES; Rated Power: 1/16W; Rating: 1%; Status: BeagleBone AI TDA4VM; Temperature: -55°C to 125°C; Datasheet: Y:\01_Cadence_Library\05_Datasheet\301010000_YAGEO_RC0402JR-070RL_Datasheet.pdf
U11 U20 U29 U30 U32 U34 = TPD4E05U06DQAR: SMD Diode Array ESD;4 Channel,6 Gbps,5.5V;USON-10; Manufacturer: TI; PN: 304060294; Package Size: USON-10; Part Type: ESD; Priority: A; Rating: 5.5V; Status: BeagleBone AI TDA4VM; Temperature: -40°C to 125°C
U12 = PCA9535RGE: SMD IC Interface;16-bit 2.3V to 5.5V I2C I/O expander with interrupt & config registers;VQFN(24); Manufacturer: TI; PN: 310071440; Status: reComputer Industrial J201; Temperature: -40°C to 85°C
C130 C132-C134 C164 C503 = CC: SMD CAP Ceramic 10uF-10V-10%-X5R;0603; Manufacturer: YAGEO; Manufacturer Part Number: CC0603KRX5R6BB106; PN: 302010103; Package Size: 0603; Part Type: Ceramic; Rating: 10V,X5R; SIGNAL_MODEL: DEFAULT_CAPACITOR_4.7e+06pF_1_2; Status: BeagleBone Carrier Board; Temperature: -55°C to 85°C
C137 C138 C140-C143 = CC: SMD CAP Ceramic 100nF-10V-10%-X5R;0201; Manufacturer: YAGEO; Manufacturer Part Number: CC0201KRX5R6BB104; PN: 302010271; Package Size: 0201; Part Type: Ceramic; Rating: 10V,X5R; SIGNAL_MODEL: DEFAULT_CAPACITOR_100000pF_1_2; Status: ODYSSEY-i.MX8M; Temperature: -55°C to 85°C
D34 = DIODE_TVS: SMD Diode Zener 5.6V-500mW;SOD-123; Manufacturer: ON; PN: 304030710; Package Size: SOD-123; Part Type: Zener Diode; Rating: 6V; Status: reTerminal DM
D36 D37 D39 D41 D42 D44 D46-D48 = DIODE_TVS_BI-DIR: SMD Diode TVS 13V-600W;DO-214AA; Manufacturer: BrightKing; PN: 304050965; Package Size: SMB; Part Type: TVS; Rating: 13V; Status: Sensecap one; Temperature: -55°C to 150°C
J21-J23 = Terminal_3P: DIP Male Screw Terminal-Green;1*3P-3.5-90D; Manufacturer: 中益电子; PN: 320112074; Package Size: 3.5mm-90D; Status: reComputer CM4 R1002; Temperature: -40°C to 105°C
L11 = L: SMD Inductor 6.8uH-20%-1.5A;L4.0xW4.0xH2.6mm; Manufacturer: Sunlord; Manufacturer Part Number: SWPA4026S6R8MT; PN: 303011409; Package Size: 4x4 mm; Part Type: Inductor; Rating: 1.5A; Status: Zola_Gateway; Temperature: -40°C to 125°C
R117 = R: SMD RES 0R-1%-1/10W;0603; Manufacturer: YAGEO; Manufacturer Part Number: RC0603FR-070RL; PN: 301012029; Package Size: 0603; Part Type: RES; Rating: 1%; Status: BBG Gateway; Temperature: -55°C to 155°C
R118 R122 = R: SMD RES 0R-±1%-1/20W;0201; Manufacturer: YAGEO; Manufacturer Part Number: RC0201FR-070RL; PN: 301010525; Package Size: 0201; Part Type: RES; Rating: 1%; Status: BeagleBone AI TDA4VM; Temperature: -55°C to 125°C; Datasheet: Y:\01_Cadence_Library\05_Datasheet\301010000_YAGEO_RC0402JR-070RL_Datasheet.pdf
R120 = R: SMD RES 15K-1%-1/20W;0201; Manufacturer: YAGEO; Manufacturer Part Number: RC0201FR-0715KL; PN: 301012913; Package Size: 0201; Part Type: RES; Rating: 1%; Status: AM62_OSM; Temperature: -55°C to 125°C
R123 = R: SMD RES 1M-1%-1/4W;1206; Manufacturer: YAGEO; Manufacturer Part Number: RC1206FR-071ML; PN: 301010410; Package Size: 1206; Part Type: RES; Rating: 1%; Status: Sensecap Gateway V1; Temperature: -55°C to 155°C
R124 R132 R133 R141 R142 R149 = R: SMD RES 10K-1%-1/10W;0603; Manufacturer: YAGEO; Manufacturer Part Number: RC0603FR-0710KL; PN: 301010299; Package Size: 0603; Part Type: RES; Rating: 1%; SIGNAL_MODEL: DEFAULT_RESISTOR_10000OHM_1_2; Status: Sensecap Gateway V1; Temperature: -55°C to 155°C
R125 R130 R135 R140 R143 R150 = R: SMD RES;10R-1/8W-1%-0805; PN: 301010583; Package Size: 0805; Status: reComputer R1002; Temperature: -55°C to 155°C
R126 R128 R134 R137 R144 R146 = R: SMD RES;33R-5%-1/20W;0201; Manufacturer: YAGEO; Manufacturer Part Number: RC0201JR-0733RL; PN: 301010675; Package Size: 0201; Part Type: RES; Rating: 5%; SIGNAL_MODEL: DEFAULT_RESISTOR_33.000000OHM_1_2; Status: BeagleBone AI TDA4VM; Temperature: -55°C to 125°C
R129 R139 R148 = R: SMD RES 120R-5%-1/4W;1206; ASSY: DNP; Manufacturer: YAGEO; Manufacturer Part Number: RC1206JR-07120RL; PN: 301011878; Package Size: 1206; Part Type: RES; Rating: 5%; Status: BeagleBone Carrier Board; Temperature: -55°C to 155°C
R131 R138 R147 R175 = R: SMD RES 10K-±1%-1/20W;0201; Manufacturer: YAGEO; Manufacturer Part Number: RC0201FR-0710KL; PN: 301010526; Package Size: 0201; Part Type: RES; Rating: 1%; Status: BeagleBone AI TDA4VM; Temperature: -55°C to 125°C
R532 = R: SMD RES 0R-5%-1/16W;0402; Manufacturer: YAGEO; Manufacturer Part Number: RC0402JR-070RL; PN: 301010000; Package Size: 0402; Rating: 5%; Status: BeagleBone Carrier Board; Temperature: -55°C to 155°C
TP32 TP34-TP37 = Test_Point: Test Point;TP35S_SMD; CLASS: DISCRETE; Company Part Status: Mini-Gateway; Status: Mini-Gateway
TP33 = Test_Point: Test Point;TP35S_SMD; Status: Mini-Gateway
U22 = Isolate_DCDC: DIP Isolated DCDC;5V to 5V,1500VDC/min,1W;4P-2.54mm-L11.60*W6.00*H10.16mm; Manufacturer: MORNSUN; PN: 310032274; Part Type: Isolated DCDC; Rating: 1W; Status: Zola Gateway; Temperature: -40°C to 105°C
U23 U31 = SY6280: SMD IC PMIC;SOT23-5; Manufacturer: SILERGY; PN: 310030260; Package Size: SOT23-5; Part Type: Power Switch; Status: R2; Temperature: -40°C to 85°C
U24 U26 U27 = ISO3082DW: SMD IC Interface RS485;WSOP-16; Manufacturer: 3Peak; PN: 310071432; Package Size: WSOP-16; Part Type: RS485; Status: reTerminal DM; Temperature: -40°C to 125°C
U25 = SN74AHC86: SMD IC XOR Logic 74HC86T14-13,TSSOP-14; Manufacturer: Diodes; PN: 310051510; Package Size: TSSOP-14; Status: reComputer CM4 R101; Temperature: -40°C to 150°C
C144 = CT: SMD CAP Aluminum 100uF-35V;D6.3*H7.7mm; Manufacturer: ST; Manufacturer Part Number: CS1V101M-CRE77; PN: 302030052; Package Size: D6.3*H7.7mm; Part Type: Aluminum; Status: BBAI
C145 = CC: SMD CAP Ceramic 10UF-50V-10%-X7R;1206; Manufacturer: Samsung; Manufacturer Part Number: CL31B106KBHNNNE; PN: 302012419; Part Type: Ceramic; Rating: 50V,X7R; Status: reTerminal DM; Temperature: -55°C to 125°C
C146 C150-C153 = CC: SMD CAP Ceramic 100nF-25V-10%-X7R;0402; Manufacturer: YAGEO; Manufacturer Part Number: CC0402KRX7R8BB104; PN: 302010024; Package Size: 0402; Part Type: Ceramic; Rating: 25V,X7R; Status: BeagleBone Carrier Board; Temperature: -55°C to 125°C
C147 C148 = CC: SMD CAP Ceramic 10nF-100V-10%-X7R;0603; Manufacturer: YAGEO; Manufacturer Part Number: CC0603KRX7R0BB103; PN: 302012962; Package Size: 0603; Part Type: Ceramic; Rating: 100V; Status: reTerminal Plus; Temperature: -55°C to 125°C
C149 = CC: SMD CAP Ceramic 10nF-100V-10%-X7R;0603; ASSY: DNP; Manufacturer: YAGEO; Manufacturer Part Number: CC0603KRX7R0BB103; PN: 302012962; Package Size: 0603; Part Type: Ceramic; Rating: 100V; Status: reTerminal Plus; Temperature: -55°C to 125°C
C154-C157 = CC: SMD CAP Ceramic 22nF-100V-10%-X7R;0603; Manufacturer: YAGEO; Manufacturer Part Number: CC0603KRX7R0BB223; PN: 302012961; Package Size: 0603; Rating: 100V,X7R; Status: STM32MP135D; Temperature: -55°C to 125°C
C158 C159 = CC: SMD CAP Ceramic 1nF-2kV-10%-X7R;1206; Manufacturer: YAGEO; Manufacturer Part Number: CC1206KKX7RDBB102; PN: 302011962; Package Size: 1206; Part Type: Ceramic; Rating: 2KV,X7R; Status: Zola_Gateway; Temperature: -55°C to 125°C
D50 = DIODE_TVS_BI-DIR: SMD Diode TVS-58VWM-93.6V;DO-214AA(SMB); Manufacturer: 君耀; PN: 304050978; Package Size: SMB; Part Type: TVS; Rating: 58V; Status: reTerminal DM; Temperature: -55°C to 150°C
D51 D52 = BRIDGE_RECTIFIERS_DF: SMD Diode;600V-1A-4P-7*4.9*3mm; Manufacturer: MDD; PN: 304010994; Package Size: SMD 4P 4.7x3.8mm; Rating: 600V; Status: reTerminal DM; Temperature: -55°C to 150°C
FB9 FB10 FB26 = FB: SMD Ferrite Bead;120R-2A;0603; CLASS: DISCRETE; Company Part Status: BeagleBone Carrier Board; Manufacturer: Murata; Manufacturer PN: BLM18PG121SN1D; Manufacturer Part Number: BLM18PG121SN1D; PN: 303030024; Package Size: 0603; Part Type: Ferrite Bead; Rating: 2A; Status: BeagleBone Carrier Board; Temperature: -55°C to 125°C
J18 = RJ45_LPJE101AGNL: DIP RJ45 W/P;12+2P-L15.8*W16.3*H12.85mm; Manufacturer: 科优达; PN: 320140656; Package Size: 12+2P-L15.8*W16.3*H12.85mm; Status: reComputer R1002; Temperature: -40°C to 85°C
L15 = L: SMD Inductor 3.3uH-20%-3.3A;2P-L4.2*W4.4*H1.8m; Manufacturer: Sunlord; Manufacturer Part Number: MWSA0402S-3R3MT; PN: 303011669; Part Type: Inductor; Rating: 3.3A; Status: reTerminal DM
L16 = CLT: SMD Common Mode Filter;3200R-0.65A;4P-L8.7*W10*H6.5mm; Manufacturer: CODACA; Manufacturer Part Number: CSTCB1060R-302; PN: 303050383; Part Type: Common Mode Filter; Rating: 650mA
R151-R154 R176 = R: SMD RES 0R-5%-1/8W;0805; Manufacturer: YAGEO; Manufacturer Part Number: RC0805JR-070RL; PN: 301010359; Package Size: 0805; Part Type: RES; Rating: 5%; Status: Sensecap Gateway V1; Temperature: -55°C to 155°C
R156-R159 = R: SMD RES 75R-1%-1/10W;0603; Manufacturer: YAGEO; Manufacturer Part Number: RC0603FR-0775RL; PN: 301010269; Package Size: 0603; Part Type: RES; Rating: 1%; Status: STM32MP135D; Temperature: -55°C to 155°C
R161 = R: SMD RES 0R-5%-1/4W;1206; Manufacturer: YAGEO; Manufacturer Part Number: RC1206JR-070RL; PN: 301010407; Package Size: 1206; Part Type: RES; Rating: 5%; Status: BeagleBone Carrier Board; Temperature: -55°C to 155°C
T1 = LP82441ANL: SMD Transformer;24P-L15.1*W10.0*H4.0mm; Manufacturer: LINK-PP; PN: 303060374; Package Size: 24P-L15.1*W10.0*H4.0mm; Status: R2; Temperature: -40°C to 125°C
U28 = Module_MQ7813: DIP PoE module;8P-2.54mm-L27.9*W17.8*H12.7mm; ASSY: DNP; Manufacturer: 英联; PN: 317990750; Rating: 12V,1.1A; Status: SenseCAP M2
C161 C167 C169 = CC: SMD CAP Ceramic 100nF-10V-10%-X5R;0201; Manufacturer: YAGEO; Manufacturer Part Number: CC0201KRX5R6BB104; PN: 302010271; Package Size: 0201; Part Type: Ceramic; Rating: 10V,X5R; Status: ODYSSEY-i.MX8M; Temperature: -55°C to 85°C
C162 = CC: SMD CAP Ceramic 100nF-50V-10%-X7R;0603; Manufacturer: YAGEO; Manufacturer Part Number: CC0603KRX7R9BB104; PN: 302010138; Package Size: 0603; Rating: 50V,X7R; Status: BeagleBone Carrier Board; Temperature: -55°C to 125°C
C163 = CC: SMD CAP Ceramic 4.7uF-6.3V-20%-X5R;0402; Manufacturer: YAGEO; Manufacturer Part Number: CC0402MRX5R5BB475; PN: 302010019; Package Size: 0402; Rating: 6.3V,X5R; Status: BeagleBone Carrier Board; Temperature: -55°C to 85°C
D61 = DIODE_TVS_BI-DIR: ASSY: DNP; Package Size: SMB; Rating: 36V; Status: Combox Pro; Temperature: -65°C to 150°C
D62 = DIODE_TVS_BI-DIR: SMD Diode TVS 5V-600W;DO-214AA; ASSY: DNP; Manufacturer: ST; PN: 304050002; Package Size: SMB; Rating: 5V; Status: Testo PoE; Temperature: -55°C to 150°C
FB27 = FB: SMD Ferrite Bead 120R-1.3A;0402; Manufacturer: Murata; Manufacturer Part Number: BLM15PD121SN1D; PN: 303030040; Package Size: 0402; Rating: 1.3A; Status: BeagleBone Carrier Board; Temperature: -55°C to 125°C
J19 J61 = Header_2x7_13P: SMD Black Male Header VERT;With Positioning,Without Pin14;2*7P-1.27-5.5-4.0mm; Manufacturer: 思拓展; Manufacturer Part Number: SF-PH-127-0030-2*7-K14-D; PN: 320021939; Package Size: 2*7P-1.27-5.5-4.0mm; Status: reComputer Industrial J201; Temperature: -40°C to 105°C
J24 = FPC_22+4P: SMD FPC CONN;22P-0.5mm;L16.7*W3.3*H3.95mm; Manufacturer: MTCONN; PN: 320060925; Package Size: 22P-0.50mm; Status: BeagleY AI; Temperature: -40°C to 85°C
J25 = JST_10+2P: SMD Male 1.0mm; 10P+2P-1.00mm-90D; Manufacturer: 思拓展; PN: 320112080; Package Size: 1.0-10P; Status: reComputer R1002; Temperature: -25°C to 70°C
Q4 = PMOS_9P: SMD MOSFET P-CH 60V-70A;PDFNWB5*6-8L; Manufacturer: CJ; PN: 305020497; Package Size: PDFNWB5*6-8L; Rating: 60V,70A; Status: reTerminal Plus; Temperature: -55°C to 150°C
Q5 = NMOS_123: SMD MOSFET N-CH 60V-300mA ;SOT-23; Manufacturer: NXP; PN: 305030028; Package Size: SOT-23; Part Type: NMOS; Rating: 60V 300mA; Status: Geni; Temperature: -65°C to 150°C
R163 = R: SMD RES 1K-±1%-1/20W;0201; CLASS: DISCRETE; Company Part Status: BeagleBone Carrier Board; Manufacturer: YAGEO; Manufacturer PN: RC0402JR-071KL; Manufacturer Part Number: RC0201FR-071KL; PN: 301010523; Package Size: 0201; Part Type: RES; Rated Power: 1/16W; Rating: 1%; Status: ST; Temperature: -55°C to 125°C
R173 = R: SMD RES 13.3K-1%-1/16W;0402; Manufacturer: YAGEO; Manufacturer Part Number: RC0402FR-0713K3L; PN: 301011829; Package Size: 0402; Rating: 1%; Status: BeagleBone Carrier Board; Temperature: -55°C to 155°C
C166 = CC: SMD CAP Ceramic 22uF-25V-20%-X5R;0805; Manufacturer: Samsung; Manufacturer Part Number: CL21A226MAQNNNE; PN: 302011928; Package Size: 0805; Part Type: Ceramic; Rating: 25V,X5R; Status: EOL; Temperature: -55°C to 85°C
C168 = CC: SMD CAP Ceramic 100nF-10V-10%-X5R;0201; ASSY: DNP; Manufacturer: YAGEO; Manufacturer Part Number: CC0201KRX5R6BB104; PN: 302010271; Package Size: 0201; Part Type: Ceramic; Rating: 10V,X5R; Status: ODYSSEY-i.MX8M; Temperature: -55°C to 85°C
J62 = PCIe_M.2_Key_M_75Pin: SMD Connector Black M.2 Key-M,PCIe Gen4.0,H=2.0mm,10u Gold Plating;67P-0.5mm; Manufacturer: FOXCONN; PN: 320111776; Rating: PCIe 4.0; Status: Jetson-20-2; Temperature: -40°C to 80°C
MH7 = MHole: SMD Stud; M3铜柱, D5.56*0.3mm, 黄铜, 表面电镀锡(编带包装,带麦拉); FPLIST: pth_4_2mm_5d8,pth_4_2mm_5d8_top; Manufacturer: 雄和远景; PN: 326051030; Status: Jetson-20-2
OSC1 = OSC_4P: SMD Oscillator;32.768KHz-3.3V-30ppm;SMD-3225-4P-L3.2*W2.5*H1.1mm; ASSY: DNP; Manufacturer: Interquip; Manufacturer Part Number: 1631-L3273-BTBQYA; PN: 306020781; Package Size: 3.2x2.5x1.0mm; Part Type: Oscillator; Priority: A; Rating: 3.3V,30ppm; Status: Jetson-20-2; Temperature: -40°C to 85°C

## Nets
3V3_RS485: C136.1 C137.1 C139.1 C140.1 C142.1 R532.2 U24.1(VCC1) U25.14(VCC) U26.1(VCC1) U27.1(VCC1)
5V_ISO_INPUT: C132.1 L11.1 U23.1(OUT)
5V_ISO_OUT: C134.1 C138.1 C141.1 C143.1 R117.2 R118.1 R124.1 R133.1 R142.1 TP32.1(TP) U24.16(VCC2) U26.16(VCC2) U27.16(VCC2)
GND: C88.2 C89.2 C90.2 C91.2 C130.2 C131.2 C132.2 C133.2 C136.2 C137.2 C139.2 C140.2 C142.2 C144.2 C145.2 C146.2 C150.2 C151.2 C152.2 C153.2 C159.1 C160.2 C161.2 C163.2 C164.2 C165.2 C166.2 C167.2 C168.2 C169.2 C503.2 C504.2 D61.1 D62.1 J10.8(GND) J19.2 J19.4 J19.6 J19.8 J19.10 J19.12 J24.1 J24.4 J24.7 J24.10 J24.13 J24.16 J24.19 J24.SH1 J24.SH2 J24.SH3 J24.SH4 J25.10 J61.1 J61.2 J61.3 J61.5 J61.7 J61.8 J61.10 J61.12 J61.13 J62.1(GND) J62.3(GND) J62.9(GND) J62.15(GND) J62.21(GND) J62.27(GND) J62.33(GND) J62.39(GND) J62.45(GND) J62.51(GND) J62.57(GND) J62.71(GND) J62.73(GND) J62.75(GND) J62.76(SH1) J62.77(SH2) MH7.1(NC) OSC1.2(GND) Q5.2(S) R92.2 R93.2 R119.2 R120.2 R123.1 R131.2 R138.2 R147.2 R161.1 R164.2 R173.2 R174.2 U11.3(GND1) U11.8(GND2) U12.9(GND) U12.25(EPAD) U20.3(GND1) U20.8(GND2) U22.1(VIN-) U23.2(GND) U24.2(GND1_1) U24.7(GND1_2) U24.8(GND1_3) U25.7(GND) U25.11(4Y) U25.12(4A) U25.13(4B) U26.2(GND1_1) U26.7(GND1_2) U26.8(GND1_3) U27.2(GND1_1) U27.7(GND1_2) U27.8(GND1_3) U28.3(VOUT-) U29.3(GND1) U29.8(GND2) U30.3(GND1) U30.8(GND2) U31.2(GND) U32.3(GND1) U32.8(GND2) U34.3(GND1) U34.8(GND2) ; also on sheet 4 5 6 7 8 9 10 11 12 13
GND_EARTH: C158.2 C159.2 J10.13(SHD1) J10.14(SHD2) J18.13(SHD1) J18.14(SHD2) J25.S1 J25.S2 R161.2 ; also on sheet 4 9 10 11
GND_ISO: C134.2 C138.2 C141.2 C143.2 D34.1(A) D36.2 D39.1 D41.2 D44.1 D46.2 D48.1 J21.3 J22.3 J23.3 R123.2 R132.2 R141.2 R149.2 U22.3(VOUT-) U24.9(GND2_3) U24.10(GND2_2) U24.15(GND2_1) U26.9(GND2_3) U26.10(GND2_2) U26.15(GND2_1) U27.9(GND2_3) U27.10(GND2_2) U27.15(GND2_1)
VDD33_HUB1: R78.1 R79.1 R80.1 R81.1 ; also on sheet 8
VDD_3V3_PCIe: C166.1 C167.1 C168.1 C169.1 J62.2(3.3_V) J62.4(3.3_V) J62.12(3.3_V) J62.14(3.3_V) J62.16(3.3_V) J62.18(3.3_V) J62.70(3.3_V) J62.72(3.3_V) J62.74(3.3_V) OSC1.1(EN) OSC1.4(VDD) R175.1 R176.2
VDD_3V3_SYS: C89.1 C90.1 C91.1 C163.1 C503.1 C504.1 FB9.1 FB26.2 FB27.2 R85.1 R88.1 R89.1 R90.1 R176.1 R532.1 U12.21(VCC) ; also on sheet 4 5 7 8 9 11 12 13
VDD_5V_OUT: C161.1 D62.2 J19.7 J19.9 J19.11 U31.1(OUT)
VDD_5V_OUT_CTL: R174.1 U12.12(P12) U31.4(EN)
VDD_5V_SYS: C130.1 C131.1 FB10.1 U23.5(IN) ; also on sheet 5 6 9 10 12
VDD_IN: C162.1 Q4.1(S1) Q4.2(S2) Q4.3(S3) R162.1 ; also on sheet 4 5
VDD_OUT: D61.2 J19.1 J19.3 J19.5 Q4.5(D1) Q4.6(D2) Q4.7(D3) Q4.8(D4) Q4.9(D5)
VDD_OUT_CTL: Q5.1(G) R164.1 U12.11(P11)
CM4_IIC0_SCL: J24.20 U34.4(CH3) U34.7(NC3) ; also on sheet 6 12
CM4_IIC0_SDA: J24.21 U34.5(CH4) U34.6(NC4) ; also on sheet 6 12
CM4_IIC5_SCL: J61.9 R88.2 U12.19(SCL) ; also on sheet 6
CM4_IIC5_SDA: J61.11 R89.2 U12.20(SDA) ; also on sheet 6
CM4_UART2_CTS: TP35.1(TP) ; also on sheet 6
CM4_UART2_RTS: R127.1 ; also on sheet 6
CM4_UART2_RXD: R126.1 ; also on sheet 6
CM4_UART2_TXD: R128.1 ; also on sheet 6
CM4_UART3_CTS: TP36.1(TP) ; also on sheet 6
CM4_UART3_RTS: R136.1 ; also on sheet 6
CM4_UART3_RXD: R134.1 U25.4(2A) ; also on sheet 6
CM4_UART3_TXD: R137.1 U25.5(2B) ; also on sheet 6
CM4_UART4_CTS: TP37.1(TP) ; also on sheet 6
CM4_UART4_RTS: R145.1 ; also on sheet 6
CM4_UART4_RXD: R144.1 U25.9(3A) ; also on sheet 6
CM4_UART4_TXD: R146.1 U25.10(3B) ; also on sheet 6
DSI1_C_N: J24.8 U32.1(CH1) U32.10(NC1) ; also on sheet 6
DSI1_C_P: J24.9 U32.2(CH2) U32.9(NC2) ; also on sheet 6
DSI1_D0_N: J24.2 U20.1(CH1) U20.10(NC1) ; also on sheet 6
DSI1_D0_P: J24.3 U20.2(CH2) U20.9(NC2) ; also on sheet 6
DSI1_D1_N: J24.5 U20.4(CH3) U20.7(NC3) ; also on sheet 6
DSI1_D1_P: J24.6 U20.5(CH4) U20.6(NC4) ; also on sheet 6
DSI1_D2_N: J24.11 U32.4(CH3) U32.7(NC3) ; also on sheet 6
DSI1_D2_P: J24.12 U32.5(CH4) U32.6(NC4) ; also on sheet 6
DSI1_D3_N: J24.14 U34.1(CH1) U34.10(NC1) ; also on sheet 6
DSI1_D3_P: J24.15 U34.2(CH2) U34.9(NC2) ; also on sheet 6
EEPROM_WP: U12.10(P10) ; also on sheet 12
Ethernet_LED2: R155.1 ; also on sheet 6
Ethernet_LED3: R160.1 ; also on sheet 6
Ethernet_Pair0_N: T1.3(TD1-) U29.2(CH2) U29.9(NC2) ; also on sheet 6
Ethernet_Pair0_P: T1.1(TD1+) U29.1(CH1) U29.10(NC1) ; also on sheet 6
Ethernet_Pair1_N: T1.6(TD2-) U29.5(CH4) U29.6(NC4) ; also on sheet 6
Ethernet_Pair1_P: T1.4(TD2+) U29.4(CH3) U29.7(NC3) ; also on sheet 6
Ethernet_Pair2_N: T1.9(TD3-) U30.2(CH2) U30.9(NC2) ; also on sheet 6
Ethernet_Pair2_P: T1.7(TD3+) U30.1(CH1) U30.10(NC1) ; also on sheet 6
Ethernet_Pair3_N: T1.12(TD4-) U30.5(CH4) U30.6(NC4) ; also on sheet 6
Ethernet_Pair3_P: T1.10(TD4+) U30.4(CH3) U30.7(NC3) ; also on sheet 6
Ethernet_RX_N: J10.3(RD+) R80.2 U11.4(CH3) U11.7(NC3) ; also on sheet 8
Ethernet_RX_P: J10.6(RD-) R81.2 U11.5(CH4) U11.6(NC4) ; also on sheet 8
Ethernet_TX_N: J10.1(TD+) R78.2 U11.1(CH1) U11.10(NC1) ; also on sheet 8
Ethernet_TX_P: J10.2(TD-) R79.2 U11.2(CH2) U11.9(NC2) ; also on sheet 8
EXT_RS485_1_A: D36.1 D37.2 J21.1 R125.2
EXT_RS485_1_B: D37.1 D39.2 J21.2 R130.2
EXT_RS485_2_A: D41.1 D42.2 J22.1 R135.2
EXT_RS485_2_B: D42.1 D44.2 J22.2 R140.2
EXT_RS485_3_A: D46.1 D47.2 J23.1 R143.2
EXT_RS485_3_B: D47.1 D48.2 J23.2 R150.2
IO_Buzzer_EN: U12.15(P15) ; also on sheet 7
ISO_5V: R117.1 U22.4(VOUT+)
LoRaWAN_SX1262_CS: U12.1(P00) ; also on sheet 13
LoRaWAN_SX1262_RST: U12.2(P01) ; also on sheet 13
LoRaWAN_SX1302_RST: U12.3(P02) ; also on sheet 13
LTE_RESET: U12.4(P03) ; also on sheet 13
nLNKA_LED: R83.1 ; also on sheet 8
nPWR_LED: J25.1 ; also on sheet 6
nSPD_LED: R84.1 ; also on sheet 8
PCIE_CLK_N: J62.53(REFCLKn) ; also on sheet 6
PCIE_CLK_NREQ: J62.52(CLKREQ#_(I/O)(0/3.3V)_or_N/C) ; also on sheet 6
PCIE_CLK_P: J62.55(REFCLKp) ; also on sheet 6
PCIE_nRST: J62.50(PERST#_(O)(0/3.3V)_or_N/C) ; also on sheet 6
PCIE_RX_N: J62.41(PERn0/SATA-B+) ; also on sheet 6
PCIE_RX_P: J62.43(PERp0/SATA-B-) ; also on sheet 6
PCIE_TX_N: J62.47(PETn0/SATA-A-) ; also on sheet 6
PCIE_TX_P: J62.49(PETp0/SATA-A+) ; also on sheet 6
PL_nLED: J25.2 ; also on sheet 6
PoE_12V: C144.1 C145.1 C146.1 TP34.1(TP) U28.1(VOUT+) U28.2(VOUT+) ; also on sheet 4
PoE_IN_N: C148.2 C149.2 D50.1 D51.2(-) D52.2(-) L16.1
PoE_IN_N1: C147.1 L16.4 U28.7(VIN-_1) U28.8(VIN-_2)
PoE_IN_P: C149.1 D51.1(+) D52.1(+) L15.2
PoE_IN_P1: C147.2 L16.3 U28.5(VIN+_1) U28.6(VIN+_2)
RS485_1_A: R124.2 R125.1 R129.1 U24.12(A)
RS485_1_B: R129.2 R130.1 R132.1 U24.13(B)
RS485_2_A: R133.2 R135.1 R139.1 U26.12(A)
RS485_2_B: R139.2 R140.1 R141.1 U26.13(B)
RS485_3_A: R142.2 R143.1 R148.1 U27.12(A)
RS485_3_B: R148.2 R149.1 R150.1 U27.13(B)
RS485_LED1: J25.6 U25.3(1Y)
RS485_LED2: J25.7 U25.6(2Y)
RS485_LED3: J25.8 U25.8(3Y)
RS485_POWER_EN: R122.1 U12.14(P14)
TPM_RST: U12.5(P04) ; also on sheet 12
TRCT: C88.1 J10.4(TCT) J10.5(RCT) J10.9(GRNA) J10.12(YELA) R82.2
UART2_RXD: R126.2 U24.3(R) U25.1(1A)
UART2_TXD: R128.2 U24.6(D) U25.2(1B)
USB2_RST_EN: U12.13(P13) ; also on sheet 9
USB_HUB1_DM2: J61.6 ; also on sheet 8
USB_HUB1_DP2: J61.4 ; also on sheet 8
USER_LED_B: J25.4 U12.8(P07)
USER_LED_G: J25.3 U12.7(P06)
USER_LED_R: J25.5 U12.6(P05)
VETH_DVDDH: C160.1 FB9.2 J18.10(GRNA) J18.12(YELA) R82.1
N21411651: C133.1 L11.2 U22.2(VIN+)
N21411770: D34.2(C) R118.2 TP33.1(TP)
N21419586: R127.2 R131.1 U24.4(\\~{R}E) U24.5(DE)
N22026897: J18.1 T1.24(MX1+)
N22026906: J18.2 T1.22(MX1-)
N22026915: J18.3 T1.21(MX2+)
N22026957: J18.7 T1.15(MX4+)
N22026966: J18.8 T1.13(MX4-)
N22027038: R153.2 R159.1 T1.14(MCT4)
N22027110: R151.2 R157.1 T1.20(MCT2)
N22027117: R154.2 R158.1 T1.17(MCT3)
N22027433: J18.11(YELC) R155.2
N22027462: J18.9(GRNC) R160.2
N22028382: R152.2 R156.1 T1.23(MCT1)
N22028488: D52.4(~1) R153.1
N22028491: D52.3(~2) R154.1
N22029929: C148.1 D50.2 L15.1 L16.2
N22030276: D51.4(~1) R151.1
N22030277: D51.3(~2) R152.1
N22038029: C154.1 R156.2
N22038032: C154.2 C155.2 C156.2 C157.2 C158.1
N22038068: C155.1 R157.2
N22038120: C156.1 R158.2
N22038172: C157.1 R159.2
N22078660: J18.6 T1.19(MX2-)
N22078676: J18.5 T1.16(MX3-)
N22078685: J18.4 T1.18(MX3+)
N22567639: C153.1 T1.11(TCT4)
N22567644: C152.1 T1.8(TCT3)
N22567654: C151.1 T1.5(TCT2)
N22567659: C150.1 T1.2(TCT1)
N22666345: R119.1 R122.2 U23.4(EN)
N22666568: R120.1 U23.3(ISET)
N23430020: R134.2 U26.3(R)
N23430038: R136.2 R138.1 U26.4(\\~{R}E) U26.5(DE)
N23430129: R137.2 U26.6(D)
N23431044: R144.2 U27.3(R)
N23431062: R145.2 R147.1 U27.4(\\~{R}E) U27.5(DE)
N23431153: R146.2 U27.6(D)
N23463209: J10.10(GRNC) R83.2
N23463212: J10.11(YELC) R84.2
N23466024: R85.2 U12.18(A0)
N23466034: R90.2 U12.22(*INT)
N23466170: R92.1 U12.23(A1)
N23466179: R93.1 U12.24(A2)
N23500588: J62.68(SUSCLK(32KHz)_(O)(0/3.3V)) OSC1.3(CLK)
N23502047: J62.54(PEWAKE#_(I/O)(0/3.3V)_or_N/C) R175.2
N23572410: C162.2 Q4.4(G) R162.2 R163.2
N23572413: Q5.3(D) R163.1
N23572753: C164.1 C165.1 FB10.2 U31.5(IN)
N23578952: R173.1 U31.3(ISET)
N23858113: FB26.1 J24.22
N23860408: FB27.1 J25.9

Not connected (* = marked no-connect by the designer): J10 7(NC)*; J19 13*; J24 17* 18*; J62 5(PERn3)* 6(N/C_1)* 7(PERp3)* 8(N/C_2)* 10(DAS/DSS#_(I/O)/LED_1#_(I)(0/3.3V))* 11(PETn3)* 13(PETp3)* 17(PERn2)* 19(PERp2)* 20(N/C_3)* 22(N/C_4)* 23(PETn2)* 24(N/C_5)* 25(PETp2)* 26(N/C_6)* 28(N/C_7)* 29(PERn1)* 30(N/C_8)* 31(PERp1)* 32(N/C_9)* 34(N/C_10)* 35(PETn1)* 36(N/C_11)* 37(PETp1)* 38(DEVSLP_(O))* 40(SMB_CLK_(I/O)(0/1.8V))* 42(SMB_DATA_(I/O)_(0/1.8V))* 44(ALERT#_(I)_(0/1.8V))* 46(N/C_12)* 48(N/C_13)* 56(N/C_14)* 58(N/C_15)* 67(N/C_16)* 69(PEDET_(NC-PCIe/GND-SATA))*; U12 16(P16)* 17(P17)*; U24 11(NC_2)* 14(NC_1)*; U26 11(NC_2)* 14(NC_1)*; U27 11(NC_2)* 14(NC_1)*; U28 4(TRIM)*

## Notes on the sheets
sheet 14
- Isolated DCDC 5V to 5V
- Imax=500mA
- Imax=6800/Rset=6800/15000=453mA
- RS485_1
- Design Note:
- Isolation Barrier:
- DR: 500kbps
- -1.25mm on top/bottom layer
  -0.25mm on inner layers
sheet 15
- RS485_2
- RS485 Connector
- Design Note:
- DR: 500kbps
- Isolation Barrier:
- -1.25mm on top/bottom layer
  -0.25mm on inner layers
- RS485_3
- Design Note:
- DR: 500kbps
- Isolation Barrier:
- -1.25mm on top/bottom layer
  -0.25mm on inner layers
sheet 16
- Imax=1.1A
- Design Note:
- PoE : 802.3af   12V@1.1A Output
- 802.3af: 12.95W
- Layout Note:
- PoE Power ：
                      Reference M2 Layout
                      Notice Creepage Distance
sheet 17
- DSI1
- LED
- Design Note:
- LED Connector
sheet 18
- Imax=3A
- Layout Note:
- PCIe Signals ：90R
sheet 19
- Schematic: reTerminal DM
- Revision History
- SHEET
- SHEET NAME
- DATE
- REVISION
- DESCRIPTION
- 01
- Title/Revision History
- 02/06/24
- v1.0
- 1. Initial
- 02
- Block Diagram
- 1. Change the UART5 to UART4 and use the HW RTS for all RS485
  direction Controll;
- 03
- Power Block Diagram
- 04
- IIC TREE
- 2. Change the DSI0 to DSI1;
- 3. Remove the reserved internal speaker Connector;
- 05
- Power IN
- 09/09/24
- v1.1
- 4. Change the user LED, buzzer control pin to GPIO expander;
- 06
- Power Management
- 5. Change the SPI0 to SPI1, I2C3 to I2C5, and reassignment of
  GPIO pins;
- 07
- BTB-200PIN
- 08
- USB2.0 Switch & RST Button
- 09
- USB2.0 HUB1
- 10
- USB2.0 HUB2 & USB A
- 11
- HDMI
- 12
- IO Expand & 10/100M Ethernet
- 13
- Type-C Debug
- 14
- RTC & Encryption & EEPROM
- 15
- Mini PICe
- 16
- RS485_1 & Isolated Power
- 17
- RS485 2&3
- 18
- Gigabit PoE
- 19
- Expander Interface & LED
- 20
- M.2 SSD
sheet 20
- Layout Note:
- Place 49.9R resistor near LAN9512
- I2C address : 0x21
